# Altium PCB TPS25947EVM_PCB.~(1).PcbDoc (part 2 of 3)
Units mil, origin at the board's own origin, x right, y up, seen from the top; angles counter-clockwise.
Board outline 6500 x 3000 mil, 4 copper layers (L1-Top Layer, L2-GND1, L3-PWR/SIG, L4-Bottom Layer), stack 63.4 mil thick; 232 components, 92 nets, 448 pads, 577 vias.

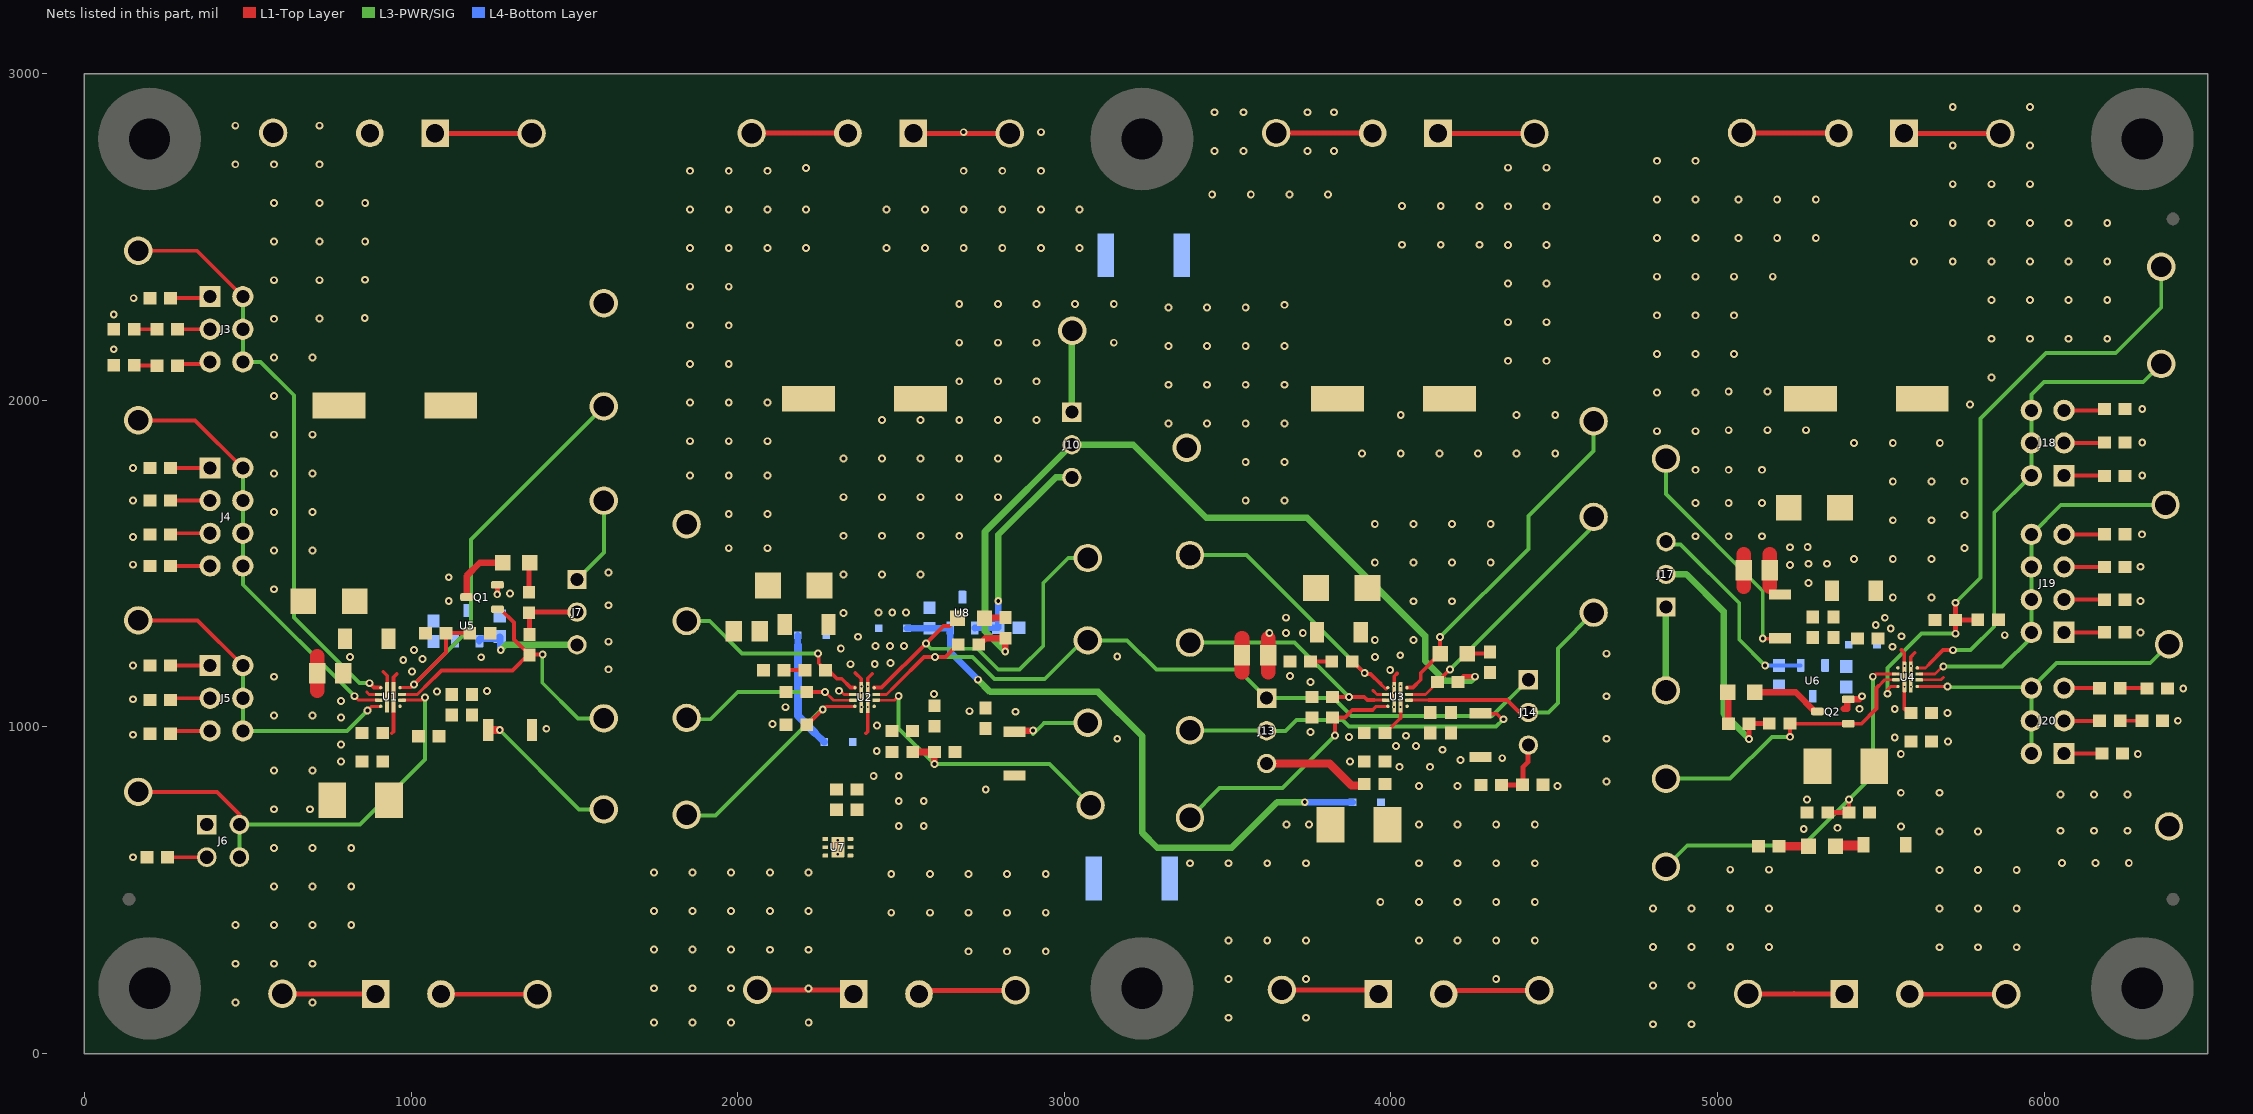
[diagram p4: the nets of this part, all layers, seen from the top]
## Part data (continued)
R38: library part CMP-0023275-5, "RES, 78.7 k, 1%, 0.1 W, 0603", Manufacturer=Yageo, Power_W=100mW, Supplier Part Number 1=311-78.7KHRCT-ND, TempCo="100 ppm/C", Tolerance_%=1%, Value2=0.1W, Value_Code=78k7, ValueDisplayed=78.7k
R39 R40: library part CMP-0016034-2, "RES, 0, 5%, 1 W, 2512", Manufacturer=Samsung, Power_W=1W, Supplier Part Number 1=1276-6000-1-ND, TempCo=ppm/C, Tolerance_%=5%, Value_Code=0000, ValueDisplayed=0
R43 R46: library part CMP-0022735-5, "RES, 100 k, 1%, 0.1 W, 0603", Manufacturer=Yageo, Power_W=100mW, Supplier Part Number 1=311-100KHRCT-ND, TempCo="100 ppm/C", Tolerance_%=1%, Value2=0.1W, Value_Code=100k
S1 S2 S3 S4: library part CMP-0002150-2, "SWITCH TACTILE SPST-NO 0.05A 12V", CurrentRating_mA=50A, Manufacturer="Omron Electronic Components", Supplier Part Number 1=SW1020CT-ND
SH-J3 SH-J4 SH-J5 SH-J6 SH-J7 SH-J10 SH-J11 SH-J12 SH-J13 SH-J16 SH-J19 SH-J20: library part CMP-0003642-1, "Shunt, 100mil, Flash Gold, Black", Manufacturer="Sullins Connector Solutions", Supplier Part Number 1=S9001-ND
TP1 TP6 TP8 TP14 TP15 TP19 TP27 TP28 TP33 TP39 TP44 TP50: library part CMP-0055148-1, "Test Point, Multipurpose, Black, TH", Color=Black, Manufacturer=Keystone, PartNumber=5011, Supplier Part Number 1=36-5011-ND
TP2 TP3 TP4 TP5 TP9 TP11 TP12 TP16 TP17 TP18 TP22 TP23 TP24 TP25 TP29 TP30 TP31 TP32 TP35 TP36 TP37 TP40 TP42 TP43 TP46 TP47 TP48 TP49: library part CMP-0055149-1, "Test Point, Multipurpose, White, TH", Color=White, Manufacturer=Keystone, PartNumber=5012, Supplier Part Number 1=36-5012-ND
TP7 TP13 TP20 TP26 TP34 TP38 TP45 TP51: library part CMP-0055147-1, "Test Point, Multipurpose, Red, TH", Color=Red, Manufacturer=Keystone, PartNumber=5010, Supplier Part Number 1=36-5010-ND
TP10 TP21 TP41: library part CMP-0055150-1, "Test Point, Multipurpose, Orange, TH", Color=Orange, Manufacturer=Keystone, PartNumber=5013, Supplier Part Number 1=36-5013-ND
U1: library part CMP-0090373-1, "2.7- 23V, 5.5 A, 28 mO Reverse Current Blocking eFuse with Input Reverse Polarity Protection", Manufacturer="Texas Instruments", Max Supply Voltage=23V, Min Supply Voltage=2.7V, Nominal Supply Current=450uA, Operating Temperature Range="-40°C to +125°C", Threshold Voltage=1.2/1.1V
U2 U3: library part CMP-0087985-1, "2.7- 23V, 5.5 A, 24.5 mO Reverse Current Blocking eFuse with Input Reverse Polarity Protection", Manufacturer="Texas Instruments", Operating Temperature Range="-40°C to +125°C"
U4: library part CMP-0088329-1, "2.7- 23V, 5.5 A, 28 mO Reverse Current Blocking eFuse with Input Reverse Polarity Protection", Manufacturer="Texas Instruments", Max Supply Voltage=23V, Min Supply Voltage=2.7V, Nominal Supply Current=0.5-6A, Operating Temperature Range="-40°C to +125°C", Output Voltage=42V, Threshold Voltage=1.2/1.1V
U5 U6 U8: library part CMP-0071020-1, "100 mA, Quasi Low-Dropout Linear Voltage Regulator, 3-pin SOT-23, Pb-Free", Manufacturer="Texas Instruments", PackageTopMarking=L0A*XTT, PowerWise=N
U7: library part CMP-0077834-1, "22-V Precision Surge Protection Clamp, DRV0006A (WSON-6)", Alternate Manufacturer="Texas Instruments"
ZZ1: library part CMP-0003616-3
ZZ2: library part CMP-0077236-1
ZZ3: library part CMP-0077237-1
ZZ4: library part CMP-0077238-1

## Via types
v1: diameter 24, hole 12, L1-Top Layer to L4-Bottom Layer, tented both sides, 551 vias
v2: diameter 12, hole 6, L1-Top Layer to L4-Bottom Layer, 24 vias
v3: diameter 19.68, hole 7.87, L1-Top Layer to L4-Bottom Layer, 2 vias

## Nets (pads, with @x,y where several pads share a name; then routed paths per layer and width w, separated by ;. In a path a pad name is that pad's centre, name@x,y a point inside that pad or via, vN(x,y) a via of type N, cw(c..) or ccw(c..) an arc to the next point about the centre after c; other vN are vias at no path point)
AUX_OFF2: J13.1 J14.1 R43.1 TP23.1 U2.3 | length 2350.3
  L1-Top Layer w9: U2.3@2423.77,1099.45 2455.77,1099.45 2483.91,1127.59
  L1-Top Layer w12: 2483.91,1127.59 2570.92,1214.6 v1(2603.81,1214.6) 2636.34,1214.6 2674.2,1252.45 R43.1@2675.18,1252.45
  L3-PWR/SIG w12: v1(2603.81,1214.6) 2718.9,1214.6 2786.32,1147.18 2940.15,1147.18 3057.88,1264.91 TP23.1@3071.9,1264.91 3192.04,1264.91 3281.74,1175.22 3532.26,1175.22 J13.1@3619.32,1088.16 3824.34,1088.16 3879.23,1033.26 4309.47,1033.26 J14.1@4420.6,1144.4
AUX_OFF3: R46.1 TP36.1 U3.3 | length 816.7
  L1-Top Layer w9: U3.3@4055.16,1099.58 4105.98,1099.58 4142.45,1136.05 R46.1@4142.45,1138.04 ; R46.1@4142.4,1138 R46.1@4142.45,1138.04 ; R46.1@4142.45,1147.02 R46.1@4142.45,1138.04 ; v1@4179.97,1175.56 v1(4180.84,1175.56)
  L1-Top Layer w12: R46.1@4142.45,1138.04 v1@4179.97,1175.56
  L3-PWR/SIG w12: v1(4180.84,1175.56) 4620.3,1615.02 TP36.1@4620.3,1642.9
dVdt1: J3.2 J3.4 J3.6 TP2.1 U1.7 | length 1812.3
  L1-Top Layer w12: TP2.1@164.8,2457.9 344.52,2457.9 J3.2@484.95,2317.47 ; v1(872.38,1133.89) 886.02,1120.25 U1.7@907.24,1120.25
  L3-PWR/SIG w12: J3.2@484.95,2317.47 J3.4@484.95,2217.47 J3.6@484.95,2117.47 539.25,2117.47 641.4,2015.32 641.4,1334.9 842.42,1133.89 v1(872.38,1133.89)
dVdt2: R44.2 TP16.1 U2.7 | length 609.5
  L1-Top Layer w12: v1(2245.8,1225) v1@2248.1,1222.7 ; 2248.1,1212.7 2248.1,1195 R44.2@2255.61,1187.49 ; R44.2@2255.61,1186.5 R44.2@2268.31,1173.8 ; R44.2@2268.31,1183.8 2304.64,1147.47 2318.49,1147.47 2345.84,1120.12 U2.7@2358.59,1120.12
  L3-PWR/SIG w12: TP16.1@1843.6,1324.2 1914.4,1324.2 2013.6,1225 v1(2245.8,1225)
dVdt3: R45.2 TP29.1 U3.7 | length 830.5
  L1-Top Layer w9: R45.2@3881.5,1200.4 R45.2@3882.48,1200.4 ; R45.2@3892.7,1200.39 R45.2@3893.68,1200.39 ; 3967.25,1132.42 3982.97,1116.7 3986.65,1116.7 U3.7@3990.2,1120.25
  L1-Top Layer w12: R45.2@3882.48,1200.4 3918.23,1164.65 v1(3919.52,1164.65) 3921.82,1162.35 3937.31,1162.35 3967.25,1132.42
  L3-PWR/SIG w12: TP29.1@3384.6,1526.27 3557.9,1526.27 v1(3919.52,1164.65)
dVdt4: J20.2 J20.4 J20.6 TP49.1 U4.7 | length 1028.5
  L1-Top Layer w9: U4.7@5611,1123.71 v1(5703.18,1123.71)
  L3-PWR/SIG w12: v1(5703.18,1123.71) 5705.48,1121.41 5957.62,1121.41 J20.6@5960.33,1118.7 ; J20.2@5960.33,918.7 J20.4@5960.33,1018.7 J20.6@5960.33,1118.7 ; TP49.1@6381.8,1252.9 6324.3,1195.4 6037.03,1195.4 J20.6@5960.33,1118.7
EN/UVLO1: C6.1 R1.1 R3.2 S1.2 TP12.1 U1.1 | length 454.4
  L1-Top Layer w25: S1.2@1236.56,990.66 1236.62,990.6 v1(1271.6,990.6)
  L3-PWR/SIG w12: v1(1271.6,990.6) 1514.82,747.38 TP12.1@1590.2,747.38
EN/UVLO2: C33.1 R25.1 R28.2 S2.2 TP24.1 U2.1 | length 240.8
  L1-Top Layer w20: S2.2@2844.31,988.12 v1@2903.87,988.12
  L3-PWR/SIG w12: v1@2904.63,978.88 2938.38,1012.63 TP24.1@3071.9,1012.63
  other v1: 2904.63,988.88
EN/UVLO3: C42.1 J13.2 R35.2 S3.2 TP31.1 U3.1 | length 1072.2
  L1-Top Layer w11: S3.2@4273.7,1041.83 4275.21,1040.32 4323.66,1040.32 4340.53,1023.46 v1(4344.04,1023.46)
  L1-Top Layer w12: TP31.1@3384.6,989.93 TP31.1@3385.49,989.04 ; J13.2@3618.43,989.04 J13.2@3619.32,988.16
  L3-PWR/SIG w12: TP31.1@3384.6,989.93 3385.49,989.04 3618.43,989.04 J13.2@3619.32,988.16 3677.49,988.16 3710.75,1021.41 3851.08,1021.41 3871.5,1000.99 4321.58,1000.99 v1(4344.04,1023.46)
EN/UVLO4: C20.1 R13.1 R15.2 S4.2 TP40.1 U4.1 | length 727.4
  L1-Top Layer w11: v1(5138.1,1270.4) 5190.16,1270.4 5190.2,1270.36 S4.2@5191.39,1271.55
  L3-PWR/SIG w12: TP40.1@4841.8,1821.31 4841.8,1713.04 5138.1,1416.74 v1(5138.1,1270.4)
FLTb2: D13.2 TP22.1 U2.4 | length 1126.4
  L1-Top Layer w12: U2.4@2417.86,1120.12 2440.89,1120.12 v1(2576.21,1255.43) 2629.96,1309.18 2649.3,1309.18 D13.2@2672.92,1332.81
  L3-PWR/SIG w12: v1(2576.21,1255.43) 2592.24,1239.4 2733.93,1239.4 2797.77,1175.56 2863.13,1175.56 2935.38,1247.8 2935.38,1440.67 3011.9,1517.2 TP22.1@3071.9,1517.2
FLTb3: D16.2 TP35.1 U3.4 | length 1062.4
  L1-Top Layer w12: U3.4@4049.25,1120.25 4066.89,1120.25 4091.12,1144.47 4091.12,1165.32 D16.2@4150.32,1224.52 v1(4150.32,1274.9)
  L3-PWR/SIG w12: v1(4150.32,1274.9) 4420.6,1545.18 4420.6,1645.28 4620.3,1844.98 TP35.1@4620.3,1935.8
GND1: C1.2 C2.2 C5.2 C6.2 C7.2 C8.2 C9.2 C10.2 C11.2 C12.2 J6.1 NT1.2 R3.1 R4.1 R6.1 R7.1 R8.1 R9.1 R10.1 S1.1 TP8.1 U1.8 | length 39.8
  L1-Top Layer w9: 864.46,1106.64 871.52,1099.58 U1.8@901.34,1099.58
  other v1: 149.31,601.16 785.4,894.17 785.4,945.8 149.31,976.18 1414.08,994.56 785.4,1029.3 785.4,1079.81 149.31,1084.81 1079.74,1108.1 1232.33,1109.56 1604.69,1176.48 149.31,1187.79 1214.81,1213.45 812.93,1214.49 1604.69,1260.97 1604.69,1372.58 1115.57,1385.38 1115.57,1458.18 1604.69,1472.58 149.31,1496.75 149.31,1581.24 149.31,1692.86 149.31,1792.86 89.8,2156.33 89.8,2262.34 150.95,2312.56
GND2: C29.2 C30.2 C32.2 C33.2 C34.2 C35.2 NT3.2 R28.1 R30.1 R31.1 S2.1 TP15.1 U2.8 | length 41.1
  L1-Top Layer w9: v1@2315.75,1108.95 2325.25,1099.45 U2.8@2352.9,1099.45
  other v1: 2759.52,808.83 3162.04,963.85 2106.44,1009.34 2850.6,1046.61 2709.35,1048.25 2146.48,1060.43 2600.86,1100.7 2310.6,1110.6 3162.04,1215.33
GND3: C38.2 C39.2 C41.2 C42.2 C43.2 C44.2 NT4.2 R35.1 R37.1 R38.1 S3.1 TP28.1 U3.8 | length 149.7
  L1-Top Layer w9: 3944.49,1112.37 3957.28,1099.58 U3.8@3984.29,1099.58
  L1-Top Layer w45: 3623.84,1167.01 NT4.2@3623.84,1219.32 3623.84,1271.64
  other v1: 4510.1,819.04 4659.88,833.47 3874.47,894.16 4212.96,899 4340.53,904.38 4158.13,930.04 4659.88,963.75 3871.67,969.62 3754.07,984.3 4659.88,1094.02 3754.07,1138.04 3690.58,1155.5 4659.88,1224.3 3627.52,1287.59 3678.76,1287.59 3730,1287.59 3678.76,1334.43
GND4: C15.2 C16.2 C19.2 C20.2 C21.2 C22.2 C23.2 C24.2 C25.2 C26.2 NT2.2 R15.1 R18.1 R20.1 R21.1 R22.1 R23.1 R36.1 S4.1 TP50.1 U4.8 | length 175.4
  L1-Top Layer w9: U4.8@5616.91,1144.38 5684.02,1144.38 5690.82,1151.18
  L1-Top Layer w45: 5159.9,1429.85 NT2.2@5159.9,1479.2 5159.9,1528.55
  other v1: 6054.4,583.4 6157.05,583.4 6258.8,583.4 6049.92,682.09 6152.57,682.09 6254.32,682.09 5263.72,687.69 5366.72,691.25 5273.92,777.55 6049.92,792.81 6152.57,792.81 6254.32,792.81 6286.35,916.68 5705.24,955.31 6408.78,1018.9 5703.23,1043.01 6425.3,1117.47 5878.98,1280.89 6294.35,1289.24 6294.35,1385.85 5278.62,1440.77 6294.35,1490.5 5221.2,1495.54 5278.18,1499.46 5334.7,1499.46 5755.98,1547.55 5221.2,1550.2 5275.62,1550.85 6299,1589.7 5755.98,1649.3 5755.98,1751.95 6300,1769.3 6300,1871.05 6300,1973.7
ILM1: J4.2 J4.4 J4.6 J4.8 TP3.1 U1.9 | length 1300.2
  L1-Top Layer w9: v1(827.35,1094.08) 839.57,1081.86 U1.9@901.34,1081.86
  L1-Top Layer w12: TP3.1@164.8,1938.7 339.1,1938.7 J4.2@484.95,1792.86
  L3-PWR/SIG w12: J4.2@484.95,1792.86 J4.4@484.95,1692.86 J4.6@484.95,1592.86 J4.8@484.95,1492.86 484.95,1436.45 v1@827.32,1094.08
ILM2: R30.2 TP17.1 U2.9 | length 610.5
  L1-Top Layer w9: R30.2@2219.8,1100.7 R30.2@2219.8,1107.2 ; v1(2267.71,1107.2) 2293.18,1081.73 U2.9@2352.9,1081.73
  L1-Top Layer w12: R30.2@2219.8,1107.2 v1(2267.71,1107.2)
  L3-PWR/SIG w12: TP17.1@1843.6,1027.6 1847.6,1023.6 1916.5,1023.6 2000.1,1107.2 v1(2267.71,1107.2)
ILM3: R37.2 TP30.1 U3.9 | length 723.6
  L1-Top Layer w9: 3948.82,1081.86 U3.9@3984.29,1081.86
  L1-Top Layer w12: R37.2@3820.8,1091.4 v1(3871.67,1091.4) 3918.23,1091.4 3927.77,1081.86 3948.82,1081.86
  L3-PWR/SIG w12: TP30.1@3384.6,1258.1 3704.97,1258.1 v1(3871.67,1091.4)
ILM4: J19.2 J19.4 J19.6 J19.8 TP48.1 U4.9 | length 1153.5
  L1-Top Layer w9: U4.9@5616.91,1162.09 5649.32,1162.09 5665.75,1162.09 5688.39,1184.73 v1(5690.82,1184.73)
  L3-PWR/SIG w12: v1(5690.82,1184.73) 5870.93,1184.73 5960.33,1274.13 J19.2@5960.33,1289.7 J19.4@5960.33,1389.7 J19.6@5960.33,1489.7 J19.8@5960.33,1589.7 6050.43,1679.8 TP48.1@6371.1,1679.8
iTimer1: J5.2 J5.4 J5.6 TP4.1 U1.10 | length 1025.1
  L1-Top Layer w9: v1(866.8,1050.14) 879.82,1063.16 901.34,1063.16
  L1-Top Layer w12: TP4.1@164.8,1326.3 346.44,1326.3 J5.2@484.95,1187.79
  L3-PWR/SIG w12: J5.2@484.95,1187.79 J5.4@484.95,1087.79 J5.6@484.95,987.79 804.45,987.79 v1(866.8,1050.14)
iTimer2: C34.1 TP18.1 U2.10 | length 718.3
  L1-Top Layer w9: C34.1@2219.8,1006.6 C34.1@2219.8,1013.1 ; v1(2260.3,1053.6) 2269.73,1063.03 U2.10@2358.81,1063.03
  L1-Top Layer w12: C34.1@2219.8,1013.1 v1(2260.3,1053.6)
  L3-PWR/SIG w12: TP18.1@1843.6,731 1845.7,728.9 1916.5,728.9 1932.35,728.9 2257.05,1053.6 v1(2260.3,1053.6)
ITimer3: C43.1 TP32.1 U3.10 | length 779.2
  L1-Top Layer w9: 3948.82,1057.25 3954.72,1063.16 U3.10@3990.2,1063.16
  L1-Top Layer w12: v1(3829.1,974.02) 3829.1,1007.86 3829.3,1008.06 3829.3,1029.19 3859.34,1029.19 3881.45,1051.3 3942.86,1051.3 3948.82,1057.25
  L3-PWR/SIG w12: TP32.1@3384.6,721.77 3475.46,812.63 3667.71,812.63 v1(3829.1,974.02)
ITimer4: J18.2 J18.4 J18.6 TP47.1 U4.10 | length 1482.2
  L1-Top Layer w9: U4.10@5611,1180.79 5636.52,1180.79 5649.32,1193.59 5649.32,1194.17
  L1-Top Layer w12: 5649.32,1194.17 5690.16,1235.01 v1(5720.94,1235.01)
  L3-PWR/SIG w12: v1(5720.94,1235.01) 5774.29,1235.01 5846.9,1307.62 5846.9,1655.87 J18.2@5960.33,1769.3 J18.4@5960.33,1869.3 J18.6@5960.33,1969.3 5960.33,2017.38 5999.15,2056.2 6303,2056.2 TP47.1@6358.1,2111.3
NetC7_1: C7.1 J5.1 | length 113
  L1-Top Layer w12: C7.1@271.93,1187.79 J5.1@384.95,1187.79
NetC8_1: C8.1 J5.3 | length 115.1
  L1-Top Layer w12: C8.1@271.93,1082.86 276.86,1087.79 J5.3@384.95,1087.79
NetC9_1: C9.1 J5.5 | length 116.6
  L1-Top Layer w12: C9.1@271.93,979.26 280.46,987.79 J5.5@384.95,987.79
NetC10_1: C10.1 J3.1 | length 123.6
  L1-Top Layer w12: C10.1@263.43,2312.56 380.03,2312.56 J3.1@384.95,2317.47
NetC11_1: C11.1 R12.1 | length 69.3
  L1-Top Layer w12: C11.1@152.8,2217.47 R12.1@222.09,2217.47
NetC12_1: C12.1 R16.1 | length 72.8
  L1-Top Layer w12: C12.1@149.8,2107.1 150.95,2105.95 R16.1@222.09,2105.95
NetC13_1: C13.1 J7.3 U5.1 | length 354.6
  L3-PWR/SIG w20: v1(1274.56,1236.05) 1289.99,1251.48 J7.3@1508.18,1251.48
  L4-Bottom Layer w20: U5.1@1209.3,1262.35 1209.3,1267.61 1211.11,1269.42 1264.53,1269.42 C13.1@1271.6,1276.5 1273.79,1274.31 1273.79,1236.81 v1(1274.56,1236.05) v1@1274.56,1237.69
NetC21_1: C21.1 J18.1 | length 116
  L1-Top Layer w12: J18.1@6060.33,1769.3 6175.03,1769.3 C21.1@6175.93,1768.4
NetC22_1: C22.1 J18.3 | length 116.3
  L1-Top Layer w12: J18.3@6060.33,1869.3 6174.18,1869.3 C22.1@6175.93,1871.05
NetC23_1: C23.1 J18.5 | length 117.4
  L1-Top Layer w12: J18.5@6060.33,1969.3 6171.53,1969.3 C23.1@6175.93,1973.7
NetC24_1: C24.1 J20.1 | length 116
  L1-Top Layer w12: J20.1@6060.33,918.7 C24.1@6176.33,918.7
NetC25_1: C25.1 R41.1 | length 66.6
  L1-Top Layer w12: R41.1@6232.46,1018.87 C25.1@6299,1018.87
NetC26_1: C26.1 R42.1 | length 73.4
  L1-Top Layer w12: R42.1@6232.42,1118.7 6304.83,1118.7 C26.1@6305.53,1118
NetC27_1: C27.1 J17.3 U6.1 | length 634.8
  L3-PWR/SIG w12: J17.3@4841.8,1567.1 4849.86,1559.04 4886.47,1559.04 5066.2,1379.31 5066.2,1267.64 v1(5145.57,1188.27)
  L4-Bottom Layer w12: v1(5145.57,1188.27) C27.1@5188.03,1188.27 5188.38,1188.62 U6.1@5254.13,1188.62
NetC28_1: C28.1 D9.1 U6.2
NetC35_1: C35.1 R44.1 | length 64.5
  L1-Top Layer w9: R44.1@2191.24,1183.87 R44.1@2191.3,1183.8
  L1-Top Layer w12: C35.1@2141.8,1173.87 R44.1@2206.24,1173.87
NetC36_1: C36.1 J10.3 U8.1 | length 647.9
  L3-PWR/SIG w20: v1(2797.8,1385.98) 2797.8,1588.1 2973.5,1763.8 J10.3@3022.9,1763.8
  L4-Bottom Layer w20: U8.1@2725.6,1302.76 2726.32,1303.47 2789.98,1303.47 C36.1@2790.7,1304.19 ; C36.1@2797.8,1303.8 v1(2797.8,1385.98)
NetC37_1: C37.1 D17.1 D18.1 U8.2 | length 1917.4
  L3-PWR/SIG w20: v1(2735.4,1144.6) 2772.8,1107.2 3103.31,1107.2 3238.95,971.55 3238.95,675.66 3284.32,630.3 3511.83,630.3 3651.13,769.6 v1(3735.96,769.6)
  L4-Bottom Layer w20: D17.1@2518.22,1301.8 2518.34,1301.92 2586.76,1301.92 C37.1@2586.88,1302.04 2587.23,1302.4 2650.44,1302.4 U8.2@2650.8,1302.76 2650.8,1229.2 v1(2735.4,1144.6) ; v1(3735.96,769.6) 3882.44,769.6 D18.1@3882.49,769.66
NetC44_1: C44.1 R45.1 | length 64.5
  L1-Top Layer w9: C44.1@3754,1200.47 C44.1@3754.07,1200.4
  L1-Top Layer w12: C44.1@3754.07,1200.4 R45.1@3818.5,1200.4
NetD3_1: D3.1 R11.1 | length 76.7
  L1-Top Layer w15: D3.1@1360.97,1489.15 1361.06,1489.06 R11.1@1361.06,1412.5
NetD3_2: D3.2 Q1.3 | length 191.8
  L1-Top Layer w20: Q1.3@1169.97,1397.68 1169.97,1462.01 1210.56,1502.6 D3.2@1280.66,1502.6
NetD4_2: D4.2 D7.2 | length 81.2
  L1-Top Layer w30: D7.2@5363.1,636.94 D4.2@5444.33,636.94
NetD7_1: D7.1 R17.2 | length 81.9
  L1-Top Layer w25: R17.2@5196.32,634.69 D7.1@5278.18,634.69
NetD8_1: D8.1 R24.1 | length 97.9
  L1-Top Layer w15: D8.1@5029.97,1106.7 D8.1@5030.66,1106
  L1-Top Layer w20: D8.1@5030.66,1106 5031.78,1104.88 5031.78,1011.12 R24.1@5032.9,1010
NetD8_2: D8.2 Q2.3 | length 219
  L1-Top Layer w15: D8.2@5111.6,1104.26 D8.2@5113.34,1106
  L1-Top Layer w20: D8.2@5113.34,1106 5238.88,1106 5297.62,1047.26 Q2.3@5305.5,1047.26
NetD10_2: D10.2 D11.2 | length 361.4
  L4-Bottom Layer w20: 2184.22,1250.2 D11.2@2184.19,1280.7
  L4-Bottom Layer w22: 2236.53,981.82 2264.84,953.51 D10.2@2265.36,954.03
  L4-Bottom Layer w25: 2184.19,1139.05 2184.19,1034.15 2236.53,981.82 ; 2184.22,1139.07 2184.22,1250.2
NetD13_1: D13.1 R26.1 | length 62.6
  L1-Top Layer w20: D13.1@2756.54,1333.75 R26.1@2819.11,1333.75
NetD16_1: D16.1 R34.1 | length 72.2
  L1-Top Layer w9: R34.1@4297.85,1224.52 R34.1@4303.03,1229.7
  L1-Top Layer w12: D16.1@4233,1224.52 R34.1@4297.85,1224.52
NetJ3_3: J3.3 R12.2 | length 99.9
  L1-Top Layer w12: R12.2@285.08,2217.47 J3.3@384.95,2217.47
NetJ3_5: J3.5 R16.2 | length 104.6
  L1-Top Layer w12: R16.2@285.08,2105.95 290.84,2111.71 379.18,2111.71 J3.5@384.95,2117.47
NetJ4_1: J4.1 R7.2 | length 113
  L1-Top Layer w12: R7.2@271.93,1792.86 J4.1@384.95,1792.86
NetJ4_3: J4.3 R8.2 | length 113
  L1-Top Layer w12: R8.2@271.93,1692.86 J4.3@384.95,1692.86
NetJ4_5: J4.5 R9.2 | length 114.5
  L1-Top Layer w12: R9.2@271.93,1589.24 275.54,1592.86 J4.5@384.95,1592.86
NetJ4_7: J4.7 R10.2 | length 113
  L1-Top Layer w12: R10.2@271.93,1492.86 J4.7@384.95,1492.86
NetJ6_3: J6.3 R6.2 | length 112
  L1-Top Layer w12: R6.2@262.67,601.16 J6.3@374.67,601.16
NetJ7_1: J7.1 TP10.1 | length 275.3
  L3-PWR/SIG w12: J7.1@1508.18,1451.48 1590.2,1533.5 TP10.1@1590.2,1692.86
NetJ7_2: J7.2 R5.2 R11.2 | length 214.3
  L1-Top Layer w15: R11.2@1360.97,1351.48 J7.2@1508.18,1351.48 ; R11.2@1361.06,1349.51 1362.32,1348.26 R5.2@1362.32,1282.98
NetJ10_1: J10.1 TP21.1 | length 247.8
  L3-PWR/SIG w20: J10.1@3023.2,1964.1 TP21.1@3023.2,2211.9
NetJ13_3: J13.3 R32.1 | length 327.7
  L1-Top Layer w25: J13.3@3619.32,888.16 3812.38,888.16 3879.52,821.02 R32.1@3919.24,821.02
NetJ14_3: J14.3 R33.1 R38.2 | length 190.5
  L1-Top Layer w15: R33.1@4338.53,822.6 R38.2@4399.94,822.6 ; R38.2@4402.5,822.8 4403.6,823.9 4403.6,876.99 4418.98,892.37 4418.98,942.78 J14.3@4420.6,944.4
NetJ17_1: J17.1 TP41.1 | length 255.5
  L3-PWR/SIG w20: TP41.1@4841.8,1111.62 J17.1@4841.8,1367.1
NetJ17_2: J17.2 R19.2 R24.2 | length 754.3
  L1-Top Layer w15: v1(5095.9,963.56) R24.2@5095.9,1010 5095.95,1010.05 5157.85,1010.05 5158.05,1010.25 R19.2@5158.2,1010.1
  L3-PWR/SIG w20: J17.2@4841.8,1467.1 4904.36,1467.1 5018,1353.45 5018,1041.46 v1(5095.9,963.56)
NetJ19_1: J19.1 R20.2 | length 115.6
  L1-Top Layer w12: J19.1@6060.33,1289.7 R20.2@6175.93,1289.7
NetJ19_3: J19.3 R21.2 | length 115.6
  L1-Top Layer w12: J19.3@6060.33,1389.7 R21.2@6175.93,1389.7
NetJ19_5: J19.5 R22.2 | length 115.6
  L1-Top Layer w12: J19.5@6060.33,1489.7 R22.2@6175.93,1489.7
NetJ19_7: J19.7 R23.2 | length 115.6
  L1-Top Layer w12: J19.7@6060.33,1589.7 R23.2@6175.93,1589.7
NetJ20_3: J20.3 R41.2 | length 109.2
  L1-Top Layer w12: J20.3@6060.33,1018.7 6060.43,1018.8 6169.33,1018.8 R41.2@6169.43,1018.9
NetJ20_5: J20.5 R42.2 | length 109.1
  L1-Top Layer w12: J20.5@6060.33,1118.7 R42.2@6169.43,1118.7
OVCSEL1: J6.2 J6.4 TP5.1 U1.2 | length 1383.7
  L1-Top Layer w9: U1.2@972.5,1082.16 1034.62,1082.16 v1(1042.69,1090.23)
  L1-Top Layer w12: TP5.1@164.8,801.16 405.94,801.16 474.67,732.43 J6.2@474.67,701.16
  L3-PWR/SIG w12: J6.4@474.67,601.16 J6.2@474.67,701.16 843.68,701.16 1042.69,900.16 v1(1042.69,1090.23)
OVLO2: R27.1 R31.2 TP25.1 U2.2 | length 958.5
  L1-Top Layer w9: U2.2@2423.77,1081.73 2480.16,1081.73 v1(2492.95,1094.53)
  L1-Top Layer w20: R27.1@2535.74,923.23 R31.2@2602.3,923.23 v1@2602.3,889.53
  L3-PWR/SIG w12: v1(2492.95,1094.53) 2492.95,995.64 2602.31,886.28 2954.43,886.28 TP25.1@3080.36,760.35
  other v1: 2602.34,886.28
OVLO3: J14.2 TP37.1 U3.2 | length 813.9
  L1-Top Layer w9: U3.2@4055.16,1081.86 4115.1,1081.86 4115.8,1082.56 ; J14.2@4420.6,1044.4 J14.2@4426.2,1050
  L1-Top Layer w12: 4115.8,1082.56 4355.32,1082.56 4393.48,1044.4 J14.2@4420.6,1044.4
  L3-PWR/SIG w12: J14.2@4420.6,1044.4 4482.33,1044.4 4510.78,1072.85 4510.78,1240.48 TP37.1@4620.3,1350
OVLO4: R14.1 R18.2 TP43.1 U4.2 | length 1251
  L1-Top Layer w9: v1(5475,1153.89) 5483.2,1162.09 U4.2@5546.04,1162.09
  L1-Top Layer w12: v1(5401.66,777.55) 5401.66,738.39 R14.1@5402.02,738.02
  L1-Top Layer w15: TP43.1@4852.64,551.91 TP43.1@4852.64,571.91 ; R18.2@5336.91,738.02 R14.1@5402.02,738.02
  L3-PWR/SIG w12: TP43.1@4841.8,571.91 4906.89,637 5261.11,637 v1(5401.66,777.55) 5475,850.89 v1(5475,1153.89)
PG1: Q1.1 R5.1 TP11.1 U1.3 | length 989.3
  L1-Top Layer w9: U1.3@972.21,1099.58 1019.08,1099.58 1042.47,1122.97 1042.69,1122.97
  L1-Top Layer w12: 1042.69,1122.97 1092.83,1173.11 1092.83,1173.33 1310.49,1173.33 1359.73,1222.57 R5.1@1362.32,1219.98 ; Q1.1@1264.46,1360.28 1273.92,1360.28 1314.99,1319.21 1314.99,1268.3 1362.32,1220.97 R5.1@1362.32,1219.98 ; v1(1402.99,1221.26) 1363.59,1221.26 R5.1@1362.32,1219.98
  L3-PWR/SIG w12: v1@1401.8,1221.26 1401.8,1135.4 1510.99,1026.21 TP11.1@1590.2,1026.21
PG4: Q2.1 R19.1 TP42.1 U4.3 | length 890.4
  L1-Top Layer w9: 5493.02,1125.68 5511.72,1144.38 U4.3@5546.04,1144.38
  L1-Top Layer w12: R19.1@5221.2,1010.1 R19.1@5221.44,1009.86 ; v1(5221.44,969.73) R19.1@5221.44,1009.86 ; 5493.02,1125.68 5486.77,1119.42 5486.77,1056.43 5440.2,1009.86 Q2.1@5399.99,1009.86 R19.1@5221.44,1009.86
  L3-PWR/SIG w12: TP42.1@4841.8,841.6 5037.9,841.6 5166.03,969.73 v1(5221.44,969.73)
PGND: C31.2 C36.2 C37.2 C40.2 D12.2 D14.2 D15.2 J8.2 J9.1 J11.2 J12.1 NT3.1 NT4.1 TP14.1 TP19.1 TP27.1 TP33.1 U7.1 U7.2 U7.3 U7.7@2306.7,631.6 U8.3 | length 1303.2
  L1-Top Layer w11: D15.2@3762.79,1433.17 D15.2@3770.75,1425.21
  L1-Top Layer w15: TP14.1@2027.1,2825.5 TP14.1@2027.85,2824.75 ; TP14.1@2042.42,2817.87 2337.12,2817.87 J8.2@2337.87,2817.12 ; TP19.1@2059.33,195.52 2060.08,194.77 2354.78,194.77 J9.1@2355.53,194.03 ; TP27.1@3648.02,2818.62 3648.77,2817.87 3943.47,2817.87 J11.2@3944.22,2817.12 ; TP33.1@3665.67,195.52 3666.42,194.77 3961.12,194.77 J12.1@3961.87,194.03
  L1-Top Layer w45: 3543.84,1167.01 NT4.1@3543.84,1219.32 3543.84,1271.64
  other v1: 2217.35,95.01 1743.45,95.41 1861.7,95.41 1979.95,95.41 3502.85,109.64 3739.36,109.64 1743.4,200.04 1861.65,200.04 1979.9,200.04 2217.3,199.64 3502.85,227.89 3739.36,227.89 1743.4,318.3 1861.65,318.3 1979.9,318.3 2099.05,317.9 2217.3,317.9 3502.85,346.14 3621.1,346.14 3739.36,346.14 2099.05,436.15 2217.3,436.15 1743.4,436.55 1861.65,436.55 1979.9,436.55 2099.05,554.4 2217.3,554.4 1743.4,554.8 1861.65,554.8 1979.9,554.8 3384.6,582.65 3502.85,582.65 3621.1,582.65 3739.36,582.65 3680.02,701.72 3749.1,701.72 1972.65,1547.21 2090.9,1547.21 1972.6,1651.85 2090.85,1651.85 3555.24,1692.84 3673.49,1692.84 1854.35,1770.1 1972.6,1770.1 2090.85,1770.1 3555.24,1811.09 3673.49,1811.09 1854.3,1874.74 1972.55,1874.74 2090.8,1874.74 3318.74,1929.34 3436.99,1929.34 3555.24,1929.34 3673.49,1929.34 1854.3,1992.99 1972.55,1992.99 2090.8,1992.99 3318.74,2047.6 3436.99,2047.6 3555.24,2047.6 3673.49,2047.6 1854.3,2111.24 1972.55,2111.24 3318.74,2165.85 3436.99,2165.85 3555.24,2165.85 3673.49,2165.85 1854.3,2229.49 1972.55,2229.49 3318.74,2284.1 3436.99,2284.1 3555.24,2284.1 3673.75,2292.3 1854.3,2347.74 1972.55,2347.74 1854.3,2466 1972.55,2466 2090.8,2466 2209.06,2466 1854.3,2584.25 1972.55,2584.25 2090.8,2584.25 2209.06,2584.25 3452.64,2630.25 3570.9,2630.25 3689.15,2630.25 3807.4,2630.25 1854.3,2702.5 1972.55,2702.5 2090.8,2702.5 2209.31,2710.7 3459.98,2763.5 3548.49,2763.5 3744.83,2763.5 3825.4,2763.5 3459.98,2881.75 3548.49,2881.75 3744.83,2881.75 3825.4,2881.75
  other v3: 2306.7,609.95 2306.7,653.25
PGND1: C3.2 C13.2 C14.2 D1.2 D2.2 J1.1 J2.2 NT1.1 Q1.2 TP1.1 TP6.1 U5.3 | length 435.9
  L1-Top Layer w9: v1@719.99,2485.19 v1@721.39,2483.79 ; v1@719.99,2603.44 v1@721.39,2602.04
  L1-Top Layer w15: TP1.1@577.8,2819 TP1.1@578.55,2818.25 ; TP6.1@595.83,183.62 596.2,183.25 597.33,182.12 J1.1@892.03,182.12 ; J2.2@873.25,2818.25 J2.2@874,2817.5 ; v1@1264.14,1406.39 Q1.2@1264.14,1434.76
  L1-Top Layer w45: 712.8,1111.49 NT1.1@712.8,1163.8 712.8,1216.11
  other v1: 462.19,156.7 698.69,156.7 462.19,274.95 580.44,274.95 698.69,274.95 462.19,393.2 580.44,393.2 698.69,393.2 816.94,393.2 580.44,511.46 698.69,511.46 816.94,511.46 580.44,629.71 698.69,629.71 816.94,629.71 580.44,747.96 691.05,748 580.44,866.21 698.69,866.21 580.44,1035.37 698.69,1035.37 580.44,1153.62 1263.82,1406.07 1303.14,1408.81 580.27,1421.62 580.27,1539.88 698.52,1539.88 580.27,1658.13 698.52,1658.13 580.27,1776.38 698.52,1776.38 580.27,1894.63 698.52,1894.63 580.27,2012.88 580.27,2131.13 698.52,2131.13 580.27,2249.39 719.29,2250.79 858.3,2252.19 580.27,2367.64 719.99,2367.64 859,2369.04 580.27,2485.89 719.99,2485.89 859.7,2485.89 580.27,2604.14 719.99,2604.14 859.7,2604.14 462.02,2722.39 580.27,2722.39 719.99,2722.39 462.02,2840.64 719.99,2840.64
PGND4: C17.2 C27.2 C28.2 D5.1 D6.2 J15.2 J16.1 NT2.1 Q2.2 R17.1 TP39.1 TP44.1 U6.3 | length 781.6
  L1-Top Layer w15: TP39.1@5074.52,2818.62 5075.27,2817.87 5369.97,2817.87 J15.2@5370.72,2817.12 ; TP44.1@5092.92,182.87 5387.62,182.87 J16.1@5388.37,182.12 ; 5233.67,184 5234.42,183.25
  L1-Top Layer w20: 5385.4,1055.5 5397.1,1055.5 5397.47,1055.87 5397.47,1082.85 Q2.2@5399.08,1084.46 ; v1(5441.9,1093.9) 5433.31,1085.31 5400.63,1085.31 Q2.2@5399.99,1084.66 ; Q2.2@5399.08,1084.46 5399.79,1084.46 Q2.2@5399.99,1084.66 ; Q2.2@5399.08,1084.46 5399.28,1084.66 Q2.2@5399.99,1084.66
  L1-Top Layer w45: 5079.9,1429.85 NT2.1@5079.9,1479.2 5079.9,1528.55
  other v1: 4802.22,89.92 4920.47,89.92 4802.22,208.18 4920.47,208.18 4802.22,326.43 4920.47,326.43 5038.72,326.43 5156.97,326.43 4802.22,444.68 4920.47,444.68 5038.72,444.68 5156.97,444.68 5038.72,562.93 5156.97,562.93 5434.8,1055.5 4932.22,1583.84 5033.87,1583.84 5135.52,1583.84 4932.22,1685.48 5033.87,1685.48 5135.52,1685.48 4932.22,1787.13 5033.87,1787.13 5135.52,1787.13 4813.97,1905.38 4932.22,1905.38 5033.87,1908.47 5152.12,1908.47 5270.37,1908.47 4813.97,2023.63 4932.22,2023.63 5033.87,2026.72 5152.12,2026.72 4813.97,2141.89 4932.22,2141.89 5050.47,2141.89 4813.97,2260.14 4932.22,2260.14 5050.47,2260.14 4813.97,2378.39 4932.22,2378.39 5050.47,2378.39 5168.73,2378.39 4813.97,2496.64 4932.22,2496.64 5064,2496.64 5182.25,2496.64 5300.51,2496.64 4813.97,2614.89 4932.22,2614.89 5064,2614.89 5182.25,2614.89 5300.51,2614.89 4813.97,2733.14 4932.22,2733.14
PGTH1: R2.1 R4.2 TP9.1 U1.4 | length 1414
  L1-Top Layer w9: U1.4@966.3,1120.25 999.43,1120.25 v1(1009.27,1130.09) ; R4.2@1177.97,1288.82 R4.2@1179.68,1287.11 R4.2@1181.42,1285.37
  L1-Top Layer w12: v1(1009.27,1130.09) 1107.04,1227.86 R2.1@1107.04,1287.12 R4.2@1179.68,1287.11
  L3-PWR/SIG w12: v1(1009.27,1130.09) 1183.2,1304.01 1183.2,1574.35 TP9.1@1590.2,1981.35
PGTH4: R29.1 R36.2 TP46.1 U4.4 | length 1957.2
  L1-Top Layer w9: v1(5519.99,1101.72) 5519.99,1113.87 5529.83,1123.71 U4.4@5551.95,1123.71
  L1-Top Layer w15: v1(5728.3,1285.5) R29.1@5728.3,1327.4 v1(5728.3,1380.08) ; R29.1@5728.8,1327.9 R29.1@5731.5,1327.9 ; R29.1@5732,1327.4 R29.1@5731.5,1327.9 ; R36.2@5795.8,1327.9 R29.1@5731.5,1327.9 ; R36.2@5799.5,1327.9 R36.2@5800,1328.4
  L3-PWR/SIG w12: v1(5519.99,1101.72) 5519.99,1181 5624.48,1285.5 v1(5728.3,1285.5) ; v1(5728.3,1380.08) 5805.02,1456.8 5805.02,1944.82 6004.59,2144.4 6218.64,2144.4 6358.1,2283.86 TP46.1@6358.1,2408.91
VCC: J10.2 R26.2 R34.2 R43.2 R46.2 | length 2539.6
  L1-Top Layer w15: R46.2@4205.4,1138 4221.24,1153.85 v1(4257.16,1153.85)
  L1-Top Layer w20: R43.2@2738.17,1252.45 2739.16,1252.45 2758.41,1271.71 R26.2@2820.06,1271.71 ; v1@2819.58,1231.75 R26.2@2819.58,1271.24
  L3-PWR/SIG w20: v1(2819.11,1231.27) 2757.1,1293.28 2757.1,1598 J10.2@3022.9,1863.8 3210.79,1863.8 3434.44,1640.15 3742.85,1640.15 4104.4,1278.6 4104.4,1202.4 4165.85,1140.95 4244.26,1140.95 v1(4257.16,1153.85)
VIN1: C1.1 C2.1 C14.1 D1.1 J1.2 R1.2 TP13.1 U1.5 U5.2 | length 496
  L1-Top Layer w11: C2.1@921.86,983.17 C2.1@921.86,989.67 ; 941.3,980.48 946.42,985.6 946.42,1090.72 946.42,1090.91 946.42,1103.56 946.42,1152.24 956.12,1161.94
  L1-Top Layer w11.8: C2.1@921.61,980.48 C2.1@926.73,985.6
  L1-Top Layer w15: J1.2@1092.4,181.75 TP13.1@1387.1,181.75
  other v1: 1003.16,1169.98 976.14,1204.82 1034.62,1207.69 1009.27,1235.76
VIN2: C29.1 C30.1 D10.1 D17.2 J9.2 R25.2 R27.2 R39.1 TP26.1 U2.5 U7.4 U7.5 U7.6 | length 485
  L1-Top Layer w11: 2392.86,980.35 2397.98,985.47 2397.98,1090.59 2397.98,1090.78 2397.99,1149.27 2411.58,1162.86
  L1-Top Layer w15: J9.2@2555.9,193.65 TP26.1@2850.6,193.65
  other v1: 2706.68,313.1 2824.93,313.1 2943.18,313.1 2470.17,431.35 2588.42,431.35 2706.68,431.35 2824.93,431.35 2943.18,431.35 2470.17,549.6 2588.42,549.6 2706.68,549.6 2824.93,549.6 2943.18,549.6 2493.04,696.86 2569.67,696.86 2493.04,773.49 2569.67,773.49 2416.4,850.13 2493.04,850.13 2425.8,926.8 2426.64,1004.42 2419.53,1192.28 2467.4,1195.95 2422.34,1247.63 2465.93,1247.63 2509.52,1247.63 2431.51,1350.37 2473.17,1350.37 2514.82,1350.37
  other v2: 2398.23,1060.43 2398.23,1082.43 2398.23,1103.43 2398.23,1124.43
VIN3: C38.1 C39.1 D14.1 D18.2 J12.2 R32.2 R33.2 R39.2 TP38.1 U3.5 | length 420.8
  L1-Top Layer w11: C38.1@3989.81,981.66 3989.81,988.16 4028.63,1026.97 4029.57,1026.97 U3.5@4029.57,1090.72
  L1-Top Layer w15: J12.2@4162.25,193.65 TP38.1@4456.95,193.65
  other v1: 4322,227.89 4085.5,346.14 4203.75,346.14 4322,346.14 4440.26,346.14 3967.25,464.39 4085.5,464.39 4203.75,464.39 4322,464.39 4440.26,464.39 4085.5,582.65 4203.75,582.65 4322,582.65 4440.26,582.65 4085.5,700.9 4203.75,700.9 4322,700.9 4440.26,700.9 4085.5,819.15 4203.75,819.15 4025.61,877.95 4119.18,877.95 4015.71,941.45 4076.12,941.45 4045.6,973
  other v2: 4029.63,1060.56 4029.63,1082.56 4029.63,1103.56 4029.62,1124.56
VIN4: C15.1 C16.1 D4.1 D5.2 D9.2 J16.2 R13.2 R14.2 TP51.1 U4.5 | length 495.5
  L1-Top Layer w11: 5562.85,1235.43 5571.63,1226.65 U4.5@5571.63,1153.24 5571.63,1054.38 C16.1@5583,1043.01
  L1-Top Layer w15: J16.2@5588.75,181.75 TP51.1@5883.45,181.75
  other v1: 5678.96,325.43 5797.21,325.43 5915.46,325.43 5678.96,443.68 5797.21,443.68 5915.46,443.68 5678.96,561.93 5797.21,561.93 5915.46,561.93 5678.96,680.18 5797.21,680.18 5561.4,694.73 5560.71,798.43 5678.96,798.43 5560.71,916.68 5542.1,967.6 5542.3,1054.7 5535.81,1245.47 5562.85,1277.7 5529.83,1301.7 5484.03,1312.13 5511.72,1334.18
  other v2: 5571.57,1123.07 5571.57,1145.07 5571.57,1166.07 5571.57,1187.07
VOUT1: C3.1 C5.1 D2.1 J2.1 R2.2 TP7.1 U1.6 | length 377.9
  L1-Top Layer w11: 914.57,1168.81 926.93,1156.45 U1.6@926.93,1090.72
  L1-Top Layer w15: J2.1@1074.38,2817.13 TP7.1@1369.08,2817.13
VOUT2: C31.1 C32.1 D11.1 D12.1 J8.1 R40.1 TP20.1 U2.6 | length 376.8
  L1-Top Layer w11: 2360.18,1165.1 2378.09,1147.2 2378.09,1090.99 U2.6@2378.49,1090.59
  L1-Top Layer w15: J8.1@2538.25,2816.75 TP20.1@2832.95,2816.75
  other v1: 2345.09,1192.14 2315.75,1239.9 2368.65,1276.13 2323.64,1348.55 2323.64,1466.8 2441.89,1466.8 2560.15,1466.8 2323.64,1585.06 2441.89,1585.06 2560.15,1585.06 2678.4,1585.06 2323.64,1703.31 2441.89,1703.31 2560.15,1703.31 2678.4,1703.31 2796.65,1703.31 2323.64,1821.56 2441.89,1821.56 2560.15,1821.56 2678.4,1821.56 2796.65,1821.56 2441.89,1939.81 2560.15,1939.81 2678.4,1939.81 2796.65,1939.81 2914.9,1939.81 2678.4,2058.06 2796.65,2058.06 2914.9,2058.06 2678.4,2176.31 2796.65,2176.31 2914.9,2176.31 3151.4,2176.31 2678.4,2294.57 2796.65,2294.57 2914.9,2294.57 3033.15,2294.57 3151.4,2294.57 2455.35,2466 2573.6,2466 2691.86,2466 2810.11,2466 2928.36,2466 3046.61,2466 2455.35,2584.25 2573.6,2584.25 2691.86,2584.25 2810.11,2584.25 2928.36,2584.25 3046.61,2584.25 2691.86,2702.5 2810.11,2702.5 2928.36,2702.5 2691.86,2820.76 2928.36,2820.76
  other v2: 2378.43,1060.43 2378.43,1082.43 2378.43,1103.43 2378.43,1124.43
VOUT3: C40.1 C41.1 D15.1 J11.1 R40.2 TP34.1 U3.6 | length 371
  L1-Top Layer w11: U3.6@4009.88,1090.72 4009.88,1154.95 4018.44,1163.51
  L1-Top Layer w15: J11.1@4144.6,2816.75 TP34.1@4439.3,2816.75
  other v1: 3997.52,1173.93 3951.5,1214.6 4028.35,1219.4 3950.45,1266.56 4068.7,1266.56 4068.7,1384.81 4186.96,1384.81 3950.45,1503.06 4068.7,1503.06 4186.96,1503.06 4305.21,1503.06 3950.45,1621.31 4068.7,1621.31 4186.96,1621.31 4305.21,1621.31 3911.72,1837.08 4029.97,1837.08 4148.22,1837.08 4266.47,1837.08 4384.72,1837.08 4502.97,1837.08 4029.97,1955.33 4384.72,1955.33 4502.97,1955.33 4358,2120.8 4476.25,2120.8 4358,2239.05 4476.25,2239.05 4358,2357.3 4476.25,2357.3 4034.17,2476.05 4152.42,2476.05 4270.68,2476.05 4358,2475.56 4476.25,2475.56 4034.17,2594.3 4152.42,2594.3 4270.68,2594.3 4358,2593.81 4476.25,2593.81 4358,2712.06 4476.25,2712.06
  other v2: 4009.83,1060.56 4009.83,1082.56 4009.83,1103.56 4009.83,1124.56
VOUT4: C17.1 C19.1 D6.1 J15.1 R29.2 TP45.1 U4.6 | length 373.2
  L1-Top Layer w11: U4.6@5591.32,1153.24 5591.72,1153.64 5591.72,1214.69 5603.68,1226.65
  L1-Top Layer w15: J15.1@5571.1,2816.75 TP45.1@5865.8,2816.75
  other v1: 5536.2,1396.29 5654.45,1396.29 5417.95,1514.55 5536.2,1514.55 5654.45,1514.55 5536.2,1632.8 5654.45,1632.8 5536.2,1751.05 5654.45,1751.05 5417.95,1869.3 5536.2,1869.3 5680.2,1869.4 5772.7,1987.55 5838,2070.25 5838,2188.5 5956.26,2188.5 6074.51,2188.5 6192.76,2188.5 5838,2306.75 5956.26,2306.75 6074.51,2306.75 6192.76,2306.75 5601.5,2425 5719.75,2425 5838,2425 5956.26,2425 6074.51,2425 6192.76,2425 5601.5,2543.26 5719.75,2543.26 5838,2543.26 5956.26,2543.26 6074.51,2543.26 6192.76,2543.26 5719.75,2661.51 5838,2661.51 5956.26,2661.51 5719.75,2779.76 5956.26,2779.76 5719.75,2898.01 5956.26,2898.01
  other v2: 5591.37,1123.07 5591.37,1145.07 5591.37,1166.07 5591.37,1187.07
pads on no net: FID1.1 FID2.1 FID3.1 FID4.1 FID5.1 FID6.1 H1.1 H2.1 H3.1 H4.1 H5.0 H6.0 H7.0 H8.0 H11.1 H12.1 H13.0 H14.0 SH-J3.0 SH-J4.0 SH-J5.0 SH-J6.0 SH-J7.0 SH-J10.0 SH-J11.0 SH-J12.0 SH-J13.0 SH-J16.0 SH-J19.0 SH-J20.0 U7.7@2306.7,613.88 U7.7@2306.7,649.32

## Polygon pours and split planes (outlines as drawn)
GND1 on L1-Top Layer "L1-TOP_LAYER_GND1_P118" (solid, remove dead copper, pour order 118): 1656.11,40.4 1671.4,55.69 1671.4,2896.7 1578.1,2990 82.9,2990 26.8,2933.9 26.8,59.6 46,40.4
VOUT1 on L1-Top Layer "L1-TOP_LAYER_VOUT1_P108" (solid, remove dead copper, pour order 108): 1068,1475.92 1164.88,1572.8 1653.8,1572.8 1671.4,1590.4 1671.4,2923 1633.7,2960.7 1632.2,2959.2 1514.55,2959.2 995.8,2959.2 970.7,2934.1 970.7,1984.01 769.39,1782.7 769.39,1325.11 773.68,1320.82 823.35,1320.82 846.15,1298.02 846.15,1171.15 862.7,1154.6 929.8,1154.6 929.8,1194.31 997.81,1262.32 1057.32,1262.32 1068,1273
GND2 on L1-Top Layer "L1-TOP_LAYER_GND2_P158" (solid, remove dead copper, pour order 158): 1691.45,2906.45 1692.66,54.52 1715.09,32.1 3159.3,32.1 3232.6,105.4 3232.6,2901.7 3173.6,2960.7 1745.7,2960.7
PGND on L1-Top Layer "L1-TOP_LAYER_PGND_P132" (solid, remove dead copper, pour order 132): 2327.2,691 2319.3,698.9 2178.35,698.9 2021.55,850.74 2021.55,1349.48 2036.83,1364.76 2170.16,1364.76 2184.96,1379.56 2184.96,1764.17 2407.5,1986.71 2407.5,2920.9 2368.74,2959.66 1727.69,2959.65 1692.04,2924.01 1692.04,55.14 1706.84,40.34 2421.04,40.34 2436.39,55.69 2436.39,301.7 2327.2,410.89
VOUT2 on L1-Top Layer "L1-TOP_LAYER_VOUT2_P142" (solid, remove dead copper, pour order 142): 3232.6,2354.29 3232.6,1408.67 3218.38,1394.45 2435.97,1394.45 2382.45,1340.92 2382.45,1137.83 2368.5,1137.83 2203.91,1302.43 2203.91,1756.12 2416.8,1969.01 2416.8,2912.85 2459.75,2955.8 3034.32,2955.8 3067.56,2923.42 3067.56,2771.06 3232.6,2606.01
VIN2 on L1-Top Layer "L1-TOP_LAYER_VIN2_P138" (solid, remove dead copper, pour order 138): 2462.26,62.25 2483.91,40.6 3035.13,40.6 3067.3,72.77 3067.3,288.81 3232.6,454.11 3232.6,763.28 3210.8,785.08 2604.25,785.08 2492.95,896.37 2492.95,1006.65 2480.37,1019.23 2422.37,1019.23 2398.06,1043.54 2394.4,1043.54 2370.09,1019.23 2350.28,1019.23 2338.82,1007.78 2338.82,622.53 2338.82,419.73 2462.26,296.29
GND4 on L1-Top Layer "L1-TOP_LAYER_GND4_P218" (solid, remove dead copper, pour order 218): 4713.4,80.2 4753,40.6 6179,40.6 6464.2,325.8 6464.2,2669.21 6175.93,2957.48 4840.08,2957.48 4713.4,2830.8
GND3 on L1-Top Layer "L1-TOP_LAYER_GND3_P174" (solid, remove dead copper, pour order 174): 3249.1,97.09 3305.58,40.6 4671.4,40.6 4695.4,64.6 4695.4,2885.6 4636,2945 3290.46,2945 3249,2903.54
VIN1 on L1-Top Layer "L1-TOP_LAYER_VIN1_P110" (solid, remove dead copper, pour order 110): 941,1190.22 1002.26,1251.48 1028.53,1251.48 1049.9,1230.11 1049.9,1193.17 1006.13,1149.4 941,1149.4
VIN1 on L1-Top Layer "L1-TOP_LAYER_VIN1_P102" (solid, remove dead copper, pour order 102): 1646.09,911.84 1671.4,886.53 1671.4,55.69 1655.41,39.7 1503.2,39.7 1015.24,39.7 999.2,55.74 999.2,271.8 887.26,383.74 887.26,637.19 887.26,1007.91 898.72,1019.36 928.76,1019.36 941,1031.6 951.8,1031.6 979.18,1004.22 1025.39,1004.22 1041.39,988.22 1041.39,940.22 1069.77,911.84
PGND4 on L1-Top Layer "L1-TOP_LAYER_PGND4_P198" (solid, remove dead copper, pour order 198): 5241.83,585.7 5217.29,610.24 5217.29,780.84 5242.85,806.4 5401.8,806.4 5413.77,818.37 5413.77,951.12 5406.54,958.35 5079.85,958.35 5054.9,983.3 5054.9,1309.99 5115.6,1370.69 5115.6,1539.62 5175.32,1599.34 5274.23,1599.34 5292,1617.11 5292,1716.02 5292,1848.56 5456.1,2012.66 5456.1,2872.6 5456.1,2921.2 5419.82,2957.48 4753.68,2957.48 4713.77,2917.57 4713.78,65.62 4739.17,40.23 5440.2,40.23 5477.17,75.84 5477.17,229.99 5477.17,448.39 5477.17,558.13 5449.6,585.7
PGND on L1-Top Layer "L1-TOP_LAYER_PGND_P136" (solid, remove dead copper, pour order 136): 4033.53,262.43 4033.53,277.8 3922.85,388.48 3922.85,727.56 3815.8,834.61 3586.66,834.61 3569.32,851.95 3569.32,1302.32 3636.74,1369.74 3865.56,1369.74 3870.51,1374.69 3870.51,1603.51 3870.51,1853.94 4005.5,1988.93 4005.5,2927.18 3987.68,2945 3290.46,2945 3249.09,2903.63 3249.09,97.1 3306.48,39.7 4004.66,39.7 4033.53,68.56 4033.53,195.15
VIN3 on L1-Top Layer "L1-TOP_LAYER_VIN3_P160" (solid, remove dead copper, pour order 160): 4307.03,797.97 4320.01,784.99 4683.34,784.99 4695.4,772.93 4695.4,287.52 4695.4,64.6 4671.03,40.23 4085.26,40.23 4066.97,58.52 4052.34,73.15 4052.34,282.71 3949.81,385.24 3949.81,804.96 3949.81,1010.2 3961.27,1021.66 4001.85,1021.66 4029.57,1049.38 4076.12,1002.83 4076.12,966.08 4179.54,862.66 4280.71,862.66 4307.03,836.34
VOUT3 on L1-Top Layer "L1-TOP_LAYER_VOUT3_P168" (solid, remove dead copper, pour order 168): 4114,1282.7 4678.65,1282.7 4695.4,1299.46 4695.4,2234.3 4695.4,2915.3 4665.7,2945 4035.36,2945 4020.79,2930.44 4020.79,2736.18 4020.79,1976.24 3885.8,1841.25 3885.8,1258.09 4011.83,1132.06 4108.98,1229.21 4108.98,1277.68
PGND1 on L1-Top Layer "L1-TOP_LAYER_PGND1_P100" (solid, remove dead copper, pour order 100): 978.2,53.6 964.3,39.7 408.7,39.7 380.95,67.45 380.95,470.16 432.76,521.98 520.38,521.98 557.2,558.79 557.2,2416 394.18,2579.02 394.18,2931.41 420.25,2957.48 932.92,2957.48 959.37,2931.03 959.37,1994.84 754.1,1789.57 754.1,870.87 790.61,834.36 855.08,834.36 872.38,817.06 872.38,376.57 978.2,270.74
PGND1 on L1-Top Layer "L1-TOP_LAYER_PGND1_P098" (solid, remove dead copper, pour order 98): 1231.53,1454.75 1225.62,1448.85 1225.62,1393.24 1229.74,1388.22 1315.32,1388.22 1325.75,1398.65 1325.75,1444.66 1315.66,1454.75
VOUT4 on L1-Top Layer "L1-TOP_LAYER_VOUT4_P206" (solid, remove dead copper, pour order 206): 5930.76,2039.26 6452.66,2039.26 6457.48,2044.08 6457.48,2891.89 6391.58,2957.79 6390.29,2956.5 5973.23,2956.5 5503.3,2956.5 5469.69,2922.89 5469.56,1998.48 5311.32,1840.24 5311.32,1588.78 5425.7,1474.4 5425.7,1404.06 5462.67,1367.1 5528.38,1367.1 5585.41,1310.07 5585.41,1193.04 5591.37,1187.07 5597.22,1192.92 5597.22,1198.53 5598.04,1198.53 5614.75,1215.24 5628.65,1215.24 5683.2,1269.8 5683.2,1791.7
VIN4 on L1-Top Layer "L1-TOP_LAYER_VIN4_P200" (solid, remove dead copper, pour order 200): 5495.1,669.31 5430.33,734.08 5430.33,969.73 5566.59,1105.99 5577.11,1105.99 5616.6,1066.5 5616.6,914.4 5843.31,687.69 6084.3,446.7 6084.3,77.38 6046.71,39.78 5535.52,39.78 5495.1,80.2
VIN4 on L1-Top Layer "L1-TOP_LAYER_VIN4_P204" (solid, remove dead copper, pour order 204): 5545.33,1226.29 5494.71,1226.29 5471.21,1249.79 5471.21,1337.1 5481.51,1347.4 5524.5,1347.4 5578.3,1293.6 5578.3,1200.5 5576.33,1198.53 5565.72,1198.53 5565.72,1205.9
EN/UVLO4 on L1-Top Layer "L1-Top Layer-EN/UVLO4" (solid, remove dead copper, pour order 202): 5498,1205.9 5551.06,1205.9 5556.64,1200.33 5556.64,1180.17 5551.94,1175.48 5457.69,1175.48 5457.1,1174.89 5396.56,1235.43 5130.88,1235.43 5123.68,1242.63 5123.68,1282.62 5134.03,1292.97 5444.53,1292.97 5452,1285.5 5452,1251.9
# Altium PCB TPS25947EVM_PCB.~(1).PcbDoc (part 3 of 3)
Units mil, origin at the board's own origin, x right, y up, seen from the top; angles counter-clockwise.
Board outline 6500 x 3000 mil, 4 copper layers (L1-Top Layer, L2-GND1, L3-PWR/SIG, L4-Bottom Layer), stack 63.4 mil thick; 232 components, 92 nets, 448 pads, 577 vias.

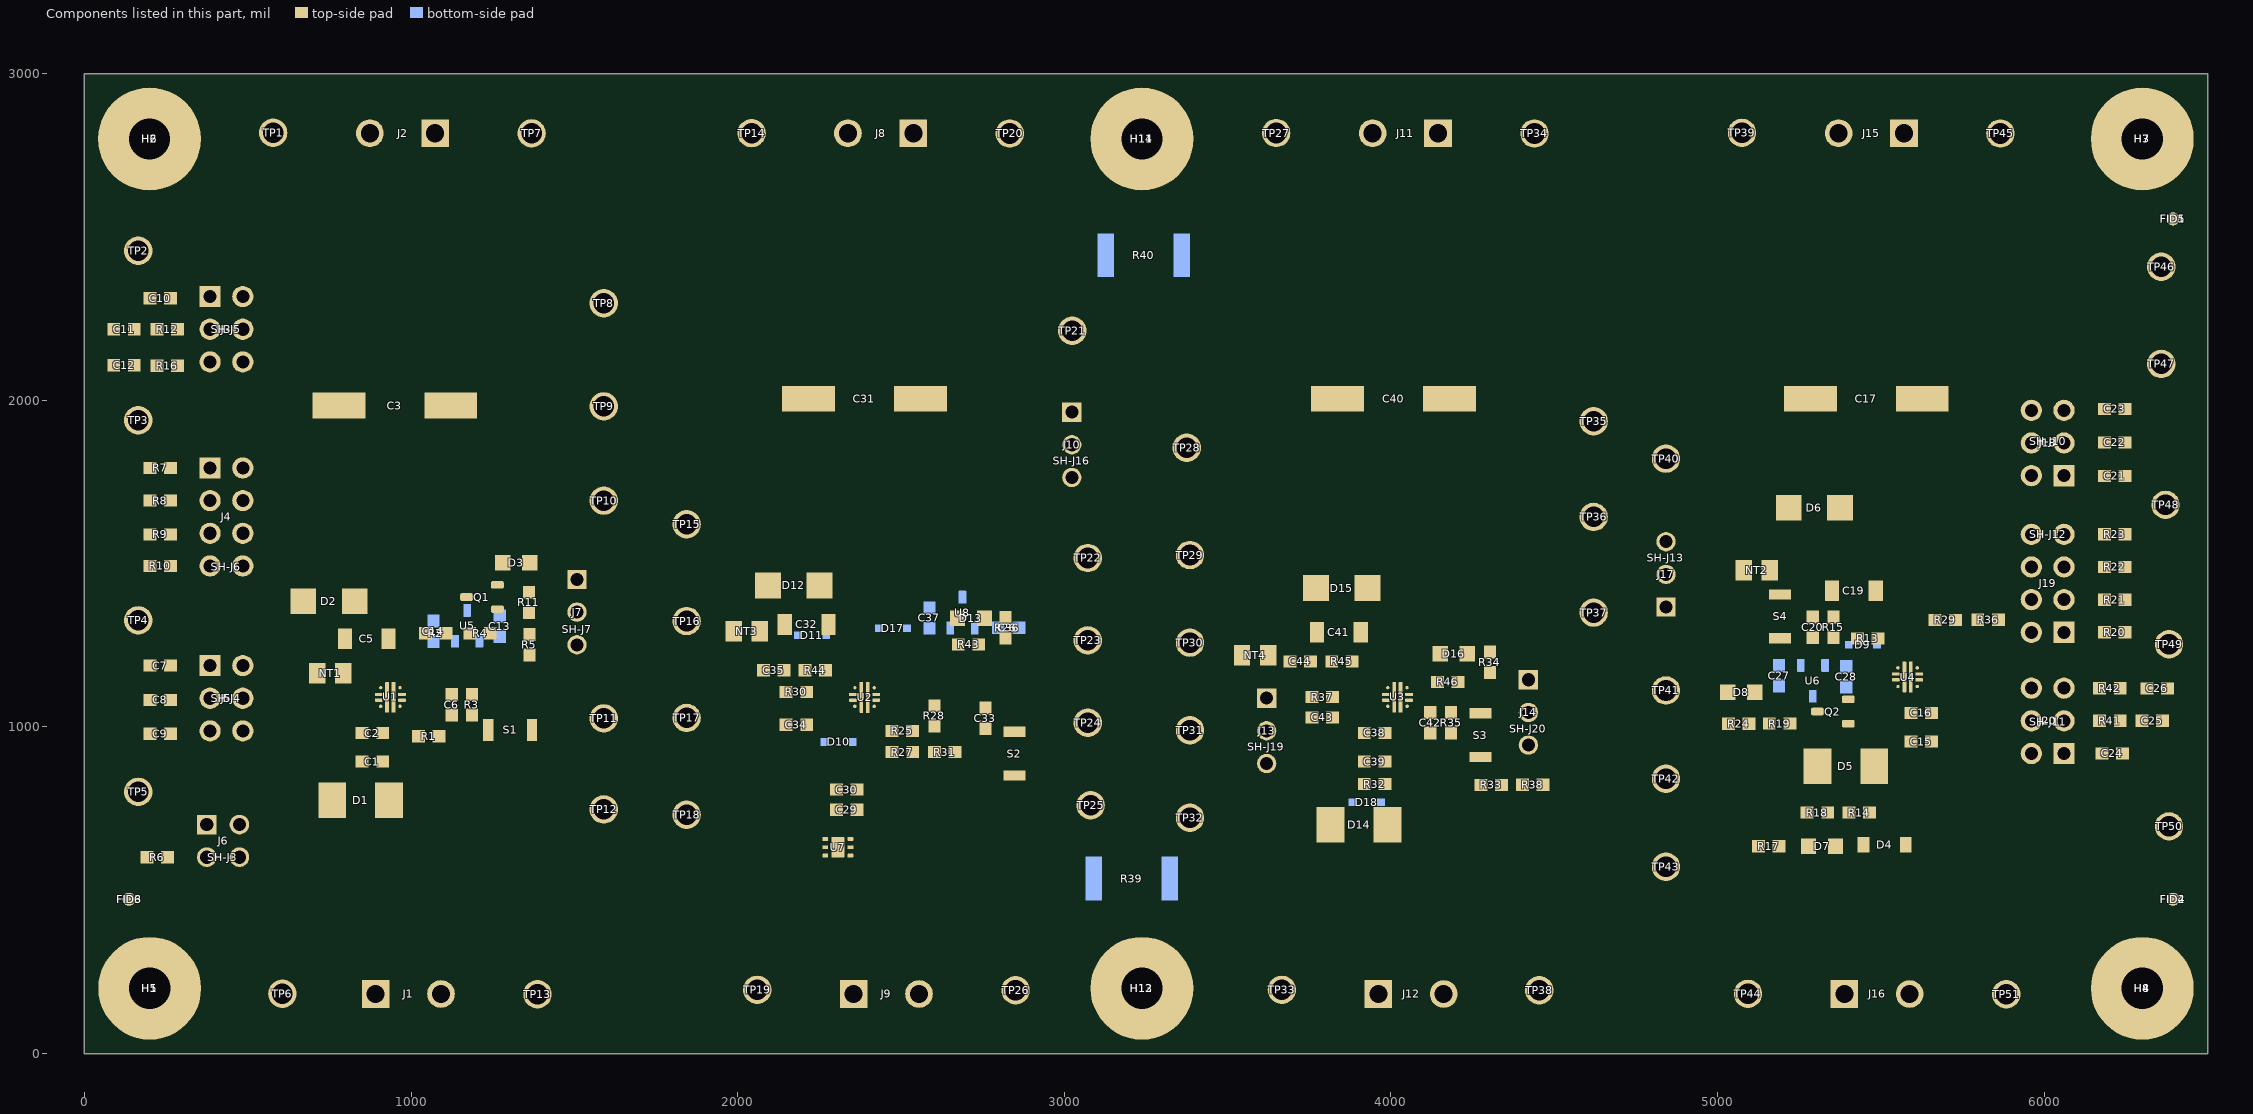
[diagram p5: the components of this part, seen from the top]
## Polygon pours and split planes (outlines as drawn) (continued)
VCC on L1-Top Layer "L1-Top Layer-VCC" (solid, remove dead copper, pour order 124): 4321.73,1186.39 4327.4,1180.72 4327.4,1109.92 4320.01,1102.53 4194.91,1102.53 4183.45,1113.98 4183.45,1175.56 4194.28,1186.39
EN/UVLO3 on L1-Top Layer "L1-TOP_LAYER_EN/UVLO3_P162" (solid, remove dead copper, pour order 162): 4212.28,1024.61 4242.87,994.02 4346.46,994.02 4358.21,1005.77 4358.21,1054.75 4348.36,1064.6 4334.62,1064.6 4139.25,1064.6 4138.63,1063.98 4070.48,1063.98 4065.39,1069.06 4045.32,1069.06 4043.94,1067.69 4043.94,1046.03 4043.35,1045.44 4064.18,1024.61
VIN2 on L1-Top Layer "L1-TOP_LAYER_VIN2_P146" (solid, remove dead copper, pour order 146): 2394.22,1137.83 2394.22,1350.37 2423,1379.15 2515.1,1379.15 2534.16,1360.1 2534.16,1239.58 2447.71,1153.13 2417.43,1153.13 2402.13,1137.83
EN/UVLO2 on L1-Top Layer "L1-TOP_LAYER_EN/UVLO2_P140" (solid, remove dead copper, pour order 140): 2915.72,949.12 2925.03,958.43 2925.03,1011.23 2917.02,1019.23 2809.39,1019.23 2557.96,1019.23 2509.11,1068.08 2422.91,1068.08 2416.88,1062.05 2416.88,1043.34 2428.82,1031.4 2484,1031.4 2513,1002.4 2513,960.76 2524.63,949.12
EN/UVLO1 on L1-Top Layer "L1-TOP_LAYER_EN/UVLO1_P106" (solid, remove dead copper, pour order 106): 984.02,1067.1 970.24,1067.1 966.3,1063.16 966.3,1046.86 988.13,1025.03 1040.59,1025.03 1064.41,1001.2 1064.41,941.2 1068.58,937.03 1266.53,937.03 1282.58,953.08 1282.58,1036.03 1260.15,1058.47 992.64,1058.47
PGND1 on L4-Bottom Layer "L4-BOTTOM_LAYER_PGND1_P126" (solid, remove dead copper, pour order 126): 1580,25.8 1655.7,101.5 1655.7,2912.4 1578.1,2990 82.9,2990 26.8,2933.9 26.8,59.6 60.6,25.8
PGND on L4-Bottom Layer "L4-BOTTOM_LAYER_PGND_P226" (solid, remove dead copper, pour order 226): 4585.87,40.34 4695.4,149.87 4695.4,2885.6 4636,2945 1784.9,2945 1723,2883.1 1724.19,95.21 1779.06,40.34
VIN2 on L4-Bottom Layer "L4-BOTTOM_LAYER_VIN2_P154" (solid, remove dead copper, pour order 154): 3231.29,630.77 3222.86,639.2 2889.76,639.2 2759.52,769.44 2762.72,1034.68 2523.89,1273.51 2523.89,1369.94 2514.68,1379.15 2432.87,1379.15 2402.6,1348.88 2402.6,1045.78 2338.82,982 2338.82,399.9 2462.26,276.47 2462.26,60.02 2490.18,32.1 3090.91,32.1 3135.05,76.24 3135.05,333.15 3231.29,429.39
VOUT2 on L4-Bottom Layer "L4-BOTTOM_LAYER_VOUT2_P196" (solid, remove dead copper, pour order 196): 2960.48,1931.62 2960.48,2014.09 3004.45,2058.06 3139.81,2054.35 3232.6,2147.14 3232.6,2585.55 3212.34,2605.82 3164.54,2605.82 3141.65,2630.38 3141.65,2846.65 3033.76,2954.54 2447.81,2954.54 2439.2,2945.93 2439.2,2102.53 2226.61,1889.94 2226.61,1717.34 2226.61,1279.72 2265.99,1240.35 2295.9,1210.44 2295.9,1050.81 2312.6,1034.11 2361.86,1034.11 2382.7,1054.95 2382.7,1353.85 2425.15,1396.3 2546.45,1396.3 2957.83,1807.68
PGND4 on L4-Bottom Layer "L4-BOTTOM_LAYER_PGND4_P224" (solid, remove dead copper, pour order 224): 4713.4,862.5 4713.4,138.4 4811.2,40.6 6179,40.6 6464.2,325.8 6464.2,2894.4 6377.3,2981.3 4813.97,2981.3 4713.4,2880.73
VIN3 on L4-Bottom Layer "L4-BOTTOM_LAYER_VIN3_P166" (solid, remove dead copper, pour order 166): 4066.97,168.05 4122.26,112.75 4506.17,112.75 4547.4,156.11 4547.4,833.57 4518.32,862.66 4320.9,862.66 4091.58,1091.99 4091.68,1120.37 4074.09,1137.96 4028.95,1137.96 4023.4,1132.42 4023.4,1043.21 3949.81,969.62 3949.81,679.45 3907.03,636.67 3548.93,636.67 3260.84,636.67 3249.05,624.88 3249.05,430.58 3366.52,313.1 4031.44,313.1 4066.97,277.57
VOUT3 on L4-Bottom Layer "L4-BOTTOM_LAYER_VOUT3_P184" (solid, remove dead copper, pour order 184): 4015.9,1168.27 4042.7,1195.07 4290.4,1195.07 4517.26,1421.93 4517.26,1685.96 4517.6,2056.5 4517.6,2859.1 4491.1,2885.6 4048.8,2885.6 4025,2861.8 4025,2740.38 3964.92,2680.3 3346.83,2680.3 3260.84,2594.3 3260.84,2362.67 3284.91,2338.6 3814.08,2338.6 3885.8,2266.87 3885.8,1999.4 3885.8,1073.37 3918.42,1040.76 4001.01,1040.76 4015.9,1055.65
VOUT4 on L4-Bottom Layer "L4-BOTTOM_LAYER_VOUT4_P208" (solid, remove dead copper, pour order 208): 5931.38,2039.88 6453.27,2039.88 6457.48,2044.08 6457.48,2895.65 6393.48,2959.66 5506.46,2959.66 5490.1,2943.3 5490.1,2903.44 5490,2184.78 5311.32,2006.1 5311.32,1588.78 5425.7,1474.4 5425.7,1404.06 5462.67,1367.1 5528.38,1367.1 5585.41,1310.07 5585.41,1193.04 5585.47,1114.8 5594.29,1105.99 5651.69,1105.99 5683.2,1137.5 5683.2,1791.7
NetC28_1 on L4-Bottom Layer "L4-Bottom Layer-NetC28_1" (solid, pour order 212): 5424.95,1178.25 5412.19,1165.49 5314.78,1165.49 5303.34,1176.93 5303.34,1260.62 5309.82,1267.11 5418.51,1267.11 5424.95,1260.67
VIN4 on L4-Bottom Layer "L4-BOTTOM_LAYER_VIN4_P210" (solid, remove dead copper, pour order 210): 5577.11,1296.47 5526.18,1347.4 5481.51,1347.4 5459.4,1325.29 5459.4,998.8 5459.4,317.36 5495.1,281.66 5495.1,132.63 5506.29,121.44 5941.22,121.44 5984.29,164.51 5984.29,546.91 5839.95,691.25 5616.6,914.6 5616.6,1066.5 5577.11,1105.99
GND1 on L2-GND1 "L2-GND1_GND1_P120" (solid, remove dead copper, pour order 120): 1580,25.8 1655.7,101.5 1655.7,2912.4 1578.1,2990 82.9,2990 26.8,2933.9 26.8,59.6 60.6,25.8
GND2 on L2-GND1 "L2-GND1_GND2_P176" (solid, remove dead copper, pour order 176): 1723,96.6 1779,40.6 3167.8,40.6 3216.4,89.2 3216.4,2869.9 3126.64,2959.66 1799.56,2959.66 1723,2883.1 1723,96.4 1744.8,74.6
GND4 on L2-GND1 "L2-GND1_GND4_P180" (solid, remove dead copper, pour order 180): 4713.4,862.5 4713.4,138.4 4811.2,40.6 6179,40.6 6464.2,325.8 6464.2,2894.4 6377.3,2981.3 4863.9,2981.3 4713.4,2830.8
GND3 on L2-GND1 "L2-GND1_GND3_P178" (solid, remove dead copper, pour order 178): 3305.58,40.6 4586.13,40.6 4684.9,139.37 4684.9,2841.9 4581.8,2945 3304.32,2945 3249,2889.68 3249,97.18
PGND1 on L3-PWR/SIG "L3-PWR/SIG_PGND1_P130" (solid, remove dead copper, pour order 130): 1580,25.8 1655.7,101.5 1655.7,2912.4 1578.1,2990 82.9,2990 26.8,2933.9 26.8,59.6 60.6,25.8
PGND on L3-PWR/SIG "L3-PWR/SIG_PGND_P232" (solid, remove dead copper, pour order 232): 1755.4,39.7 4585.23,39.7 4684.9,139.37 4684.9,2841.9 4581.8,2945 1730,2945 1691.45,2906.45 1691.45,103.65
PGND4 on L3-PWR/SIG "L3-PWR/SIG_PGND4_P220" (solid, remove dead copper, pour order 220): 4713.78,862.12 4713.78,138.03 4811.58,40.23 6179.38,40.23 6464.58,325.43 6464.58,2894.02 6377.68,2980.93 4864.28,2980.93 4713.78,2830.43

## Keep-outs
Keep-Out Layer:
  circle w10: c3237.9,2800 r182.44
  circle w10: c3237.9,200.5 r182.44
  circle w10: c200,200 r182.44
  circle w10: c6300,200 r182.44
  circle w10: c6300,2800 r182.44
  circle w10: c200,2800 r182.44
  text ".Layer_Name" at 357.57,-1124.59 h60

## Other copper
L1-Top Layer:
  region net VOUT1: 921.59,1149.87 916.86,1154.6 896.25,1154.6 896.25,1165.49 904.09,1173.33 928.07,1173.33 929.8,1171.6 929.8,1152.46 932.39,1149.87 932.39,1137.87 921.59,1137.9
  region net VIN1: 951.82,1137.84 951.82,1149.84 941.02,1149.84 941.02,1137.86
  region net VIN1: 941,1043.6 941,1031.6 951.8,1031.6 951.8,1043.58
  region net PGND1: 1315.66,1454.75 1231.53,1454.75 1225.62,1448.85 1225.62,1400.38 1237.78,1388.22 1315.32,1388.22 1325.75,1398.65 1325.75,1444.66
  pour cut-out: 5246.55,666.32 5377.86,666.32 5381.67,670.13 5381.67,703.99 5374.34,711.32 5306.68,711.32 5302.8,715.2 5302.8,777.6 5293.63,786.77 5293.63,791.26 5294.4,791.26 5305.43,780.23 5305.42,719.32 5378.03,719.32 5386.53,710.82 5384.48,708.77 5384.48,658.32 5236.38,658.32 5224.78,669.92 5224.78,671.21 5230.99,671.21 5235.8,666.4
  pour cut-out: 2847.32,1377.14 2850.6,1380.42 2544.53,1380.42 2543.26,1379.15 2543.26,1052.46 2548.56,1047.16 2548.56,1158.8 2556.77,1167.01 2829.45,1167.01 2847.32,1184.88
  pour cut-out: 3218.38,1379.15 3223.07,1379.15 3232.6,1369.62 3232.6,1380.42
  pour cut-out: 4678.65,1267.41 4688.66,1267.41 4695.4,1260.67 4695.4,1271.29
  pour cut-out: 4420.6,1002.51 4376.58,1002.51 4369.03,994.96 4357.28,994.96 4352.34,999.9 4358.21,1005.77 4417.34,1005.77
  pour cut-out: 4373.51,1005.77
  pour cut-out: 4358.2,1096.6 4356.02,1096.6 4342.69,1109.92 4342.69,1256.82 4353.29,1267.41 4353.29,1268.07 4346.46,1274.9 4329.09,1274.9 4327.4,1273.21 4327.4,1096.54 4332.54,1091.4 4352.99,1091.4 4358.21,1096.62
  pour cut-out: 1397,1532.4 1395.18,1534.22 1213.34,1534.22 1141.43,1462.31 1141.43,1385.38 1149.41,1377.4 1225.29,1377.4 1236.5,1366.18 1236.5,1344.87 1241.18,1340.2 1270.93,1340.2 1296.71,1314.41 1296.71,1195.25 1291.11,1189.64 1286.89,1189.64 1286.89,1180.61 1310.49,1157.01 1353.73,1157.01 1397,1200.28
  pour cut-out: 1645.72,1557.64 1666.4,1557.64 1671.67,1552.38 1677.26,1552.38 1680.4,1555.52 1680.4,1566.48 1676.08,1570.79 1658.86,1570.79
  pour cut-out: 1645.52,927.16 1666.2,927.16 1671.47,932.42 1677.06,932.42 1680.2,929.28 1680.2,918.32 1675.88,914.01 1658.66,914.01
  pour cut-out: 1297.88,953.08 1297.88,932.4 1303.14,927.13 1303.14,921.54 1300,918.4 1289.05,918.4 1284.73,922.72 1284.73,939.94
  pour cut-out: 2170.16,1349.47 2182.73,1349.47 2191.2,1341 2197.22,1341 2199.18,1342.97 2199.18,1356.05 2195.14,1360.1 2180.79,1360.1
  region net PGND: 2326.39,590.27 2329.85,586.8 2329.85,583.58 2324.42,578.14 2287.98,578.14 2287.01,579.1 2287.01,602.07 2290.22,605.28 2290.22,678.84 2290.67,678.4 2328,678.4 2326.38,676.79
  region net VIN2: 2336.23,662.43 2336.23,598.77 2344.74,590.26 2359.51,590.26 2360.31,591.06 2360.31,666.13 2356.84,669.6 2343.4,669.6
  pour cut-out: 6187.93,354.76 6110.91,354.76 6100.64,365.03 6099.24,363.63 6099.24,352.63 6113.38,338.49 6171.66,338.49
  pour cut-out: 3150.4,2834.95
  pour cut-out: 3237.4,5.25
  pour cut-out: 798.28,845.83 863.53,845.83 871.87,854.17 871.87,848.15 864.46,840.74 803.71,840.74 798.46,846
  pour cut-out: 5444.53,1308.27 5452.87,1308.27 5455.9,1311.3 5455.9,1352.2 5455.92,1352.22 5457.85,1350.28 5457.85,1307.95 5455.9,1306 5446.79,1306
  pour cut-out: 5274.23,1584.05 5294.42,1584.05 5300.51,1577.96 5300.51,1584.3 5296.03,1588.78 5278.97,1588.78
  region net PGND4: 5377.35,1039.4 5370.21,1046.54 5370.21,1103.39 5374.79,1107.59 5428.53,1107.59 5452,1107.76 5460.58,1099.18 5460.58,1057.28 5442.7,1039.4
  pour cut-out: 5373.78,1037.12 5363.64,1047.26 5362.8,1047.26 5362.8,1107 5371.96,1116.16 5422.04,1116.16 5460.94,1115.86 5470.46,1106.34 5470.46,1063.19 5444.39,1037.12
  region net VOUT4: 5592.54,1209.06 5595.27,1209.06 5601.45,1215.24 5614.75,1215.24 5620.84,1221.34 5620.84,1248.68 5613.72,1255.8 5613.72,1254.8 5586.4,1227.47 5586.4,1215.2
  region net VIN4: 5551.06,1226.29 5565.72,1211.63 5565.72,1205.9 5571.15,1200.48 5575.59,1200.48 5577.4,1202.29 5577.4,1247.05 5551.56,1247.05 5549.98,1245.47
  region net VIN4: 5580.19,1100.77 5571.63,1109.32 5571.63,1103.7 5558.63,1090.7 5551.3,1090.7 5551.3,1081.22 5558,1074.51 5579.33,1074.51 5587.83,1083.01 5587.83,1093.13
  region net VOUT3: 4020.2,1145.1 4009.69,1134.59 3989.29,1155.5 4016.59,1155.5 4025.93,1146.16
  region net VIN3: 4032.06,1049.66 4016.81,1034.41 4023.05,1028.18 4044.93,1028.18 4035,1038.11 4035,1050
  region net VIN2: 2417.2,1153.5 2397.99,1134.29 2397.99,1149.27 2411.58,1162.86
  region net VOUT2: 2353.75,1152.59 2360.31,1152.59 2374.8,1138.1 2381.78,1145.07 2381.78,1146.99 2382.45,1147.67 2382.45,1160.8 2378.09,1165.17 2360.25,1165.17
  pour cut-out: 200,3034.45
  text ".Layer_Name" at 357.57,-1124.59 h60
L2-GND1:
  text ".Layer_Name" at 356.57,-1126.59 h60
L3-PWR/SIG:
  text ".Layer_Name" at 357.57,-1126.59 h60
L4-Bottom Layer:
  region net VIN1: 1144.3,1282.03 1026.71,1282.03 957.3,1212.63 957.3,1197.02 997.52,1156.8 1058.44,1156.8 1146.31,1244.67 1146.31,1280.03
  pour cut-out: 3934.52,969.62 3934.52,1003.03 3907.6,1029.94 3923.09,1029.94 3938.99,1014.03 3938.99,974.1
  pour cut-out: 3284.91,2323.31 3258.69,2323.31 3246.73,2311.35 3246.73,2345.75 3247.89,2346.91
  region net VOUT4: 5598.74,1105.99 5585.6,1119.13 5585.6,1208.57 5592.27,1215.24 5598.04,1215.24 5606.39,1206.89 5606.39,1113.65
  region net VIN4: 5570.12,1198.53 5577.5,1191.15 5577.5,1105.6 5591.94,1091.16 5564.21,1091.16 5556.9,1098.48 5556.9,1189.99
  region net VIN3: 4057.83,1045.42 4057.83,1125.15 4045.03,1137.96 4028.95,1137.96 4023.8,1132.82 4023.8,1032.78 4019.73,1028.71 4041.13,1028.71
  region net VOUT3: 3992.11,1040.76 4001.01,1040.76 4015.7,1055.45 4015.7,1157.69 4014.16,1159.23 3999.95,1159.23 3992.11,1151.38
  region net VOUT2: 2384.45,1213.98 2381.6,1216.82 2364.94,1200.16 2364.94,1061.06 2361.13,1057.25 2361.13,1038.72 2366.47,1038.72 2376.87,1049.12 2384.45,1056.7
  region net VIN2: 2405.84,1152.6 2414.88,1152.6 2414.88,1137.02 2412.15,1134.29 2412.15,1031.19 2409.54,1028.58 2398.18,1028.58 2392.65,1034.11 2392.65,1139.4
  text ".Layer_Name" at 357.57,-1124.59 h60

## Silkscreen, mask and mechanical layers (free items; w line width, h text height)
Top Overlay:
  circle w10: c2240.8,657.2 r2.29
  region: 4441.22,2430.42 4141.22,2430.42 4141.22,2330.42 4441.22,2330.42
  lines w6: 2265.4,1134.47 2265.4,1124.2 2268.6,1121 ; 3919.52,1222.4 3929.92,1232.8 3941.6,1232.8 ; 4247.05,866.89 4248.26,866.89 4266.47,885.1 ; 6241.83,982.37 6241.83,982.32 6256.55,967.6 6275.91,967.6 ; 1984.8,842.08 2711.6,842.08 2711.6,1213.6 2393.78,1213.6 1984.8,1213.6 1984.8,842.08
  lines w8: 1184.03,1905.52 1228.53,1905.52 ; 1206.28,1883.27 1206.28,1927.77 ; 2621.14,1913.8 2665.64,1913.8 ; 2643.39,1891.55 2643.39,1936.05 ; 4239.87,1907.89 4284.37,1907.89 ; 4262.12,1885.64 4262.12,1930.14 ; 5697.5,1905.38 5742,1905.38 ; 5719.75,1883.13 5719.75,1927.63
  lines w10: 1703.2,23.1 1703.2,2989 ; 3238,2410.68 3238,408.84 ; 4708.51,2979.9 4708.6,2630.25 ; 4708.6,2166.2 4708.6,23.25
  text "PGND4" at 5007.4,2657.2 h35
  text "PGND" at 3576.11,2656.22 h35
  text "VOUT3" at 4365.4,2655.2 h35
  text "PGND" at 1979.85,2654.4 h35
  text "VOUT2" at 2765.03,2650.12 h35
  text "VOUT1" at 1319.01,2647.84 h35
  text "VOUT4" at 5795.9,2642.73 h35
  text "PGND1" at 517.43,2641.32 h35
  text "VOUT1" at 909.6,2546.8 h35
  text "VOUT2" at 2361,2544.4 h35
  text "VOUT4" at 5392.6,2542.8 h35
  text "VOUT3" at 4188.17,2540.12 h35
  text "For evaluation only; not" at 2993.37,2500.85 h60
  text "FCC approved for resale." at 2993.37,2439.86 h60
  text "DVDT1" at 254.63,2426.72 h35
  text "DVDT1" at 544.6,2280.2 h35
  text "'.PRJ_Title'" at 4459.34,2268.32 h60
  text "PGTH4" at 6292.8,2248.6 h35
  text "PSIL100" at 4588.02,2203.94 h60
  text "E1" at 5002.41,2203.94 h60
  text "GND1" at 1525.69,2116.73 h35
  text "ITIMER4" at 6055.2,2071.2 h35
  text "VCC_EXT2" at 2898.8,2053.8 h35
  text "ILM1" at 248.23,1905.52 h35
  text "VCC" at 3094.1,1837.08 h35
  text "PGTH1" at 1526.9,1809.15 h35
  text "ILM4" at 6351.6,1804.2 h35
  text "FLTB3" at 4524.2,1769.88 h35
  text "GND3" at 3323.8,1692.4 h35
  text "ILM1" at 553.23,1679.72 h35
  text "EN/UVLO4" at 4789.43,1651.92 h35
  text "PG1" at 1271.2,1549 h35
  text "VCC_EXT1" at 1435.4,1525.6 h35
  text "AUX_OFF3" at 4421.15,1483.66 h35
  text "GND2" at 1787.05,1451.2 h35
  text "FLTB2" at 2603.81,1385.98 h35
  text "DVDT3" at 3310.6,1365.8 h35
  text "FLTB2" at 2955.4,1356.2 h35
  text "DVDT4" at 6448.98,1333.65 h35 r90
  text "TIMER1" at 258.18,1285.42 h35
  text "FLTB3" at 4081.67,1280.02 h35
  text "OVLO3" at 4534,1187 h35
  text "dvdt2" at 1749.78,1159.99 h35
  text "PG4" at 5036.76,1154.91 h35
  text "AUX_OFF2" at 2903.1,1105.4 h35
  text "ILM3" at 3331.22,1096.64 h35
  text "TIMER1" at 544.98,1014.98 h35
  text "VCC_EXT4" at 4725.6,950.8 h35
  text "PG1" at 1558.18,863.61 h35
  text "ILM2" at 1788.6,863.61 h35
  text "EN/UVLO2" at 2947,853 h35
  text "EN/UVLO3" at 3260.4,830 h35
  text "OVCSEL1" at 250.8,775.4 h35
  text "PG4" at 4789.03,675.42 h35
  text "OVLO2" at 2959.8,597.8 h35
  text "ENUVLO1" at 1420.7,579.12 h35
  text "OVCSEL1" at 550.2,563.6 h35
  text "ITIMER3" at 3280.6,558.8 h35
  text "TIMER2" at 1775.25,554.4 h35
  text "GND4" at 6328.93,530.46 h35
  text "RPP" at 5285.98,501.06 h35
  text "OVLO4" at 4772.8,398.59 h35
  text "VIN3" at 4026.43,372.52 h35
  text "VIN2" at 2404.11,372.4 h35
  text "VIN1" at 984.22,371.04 h35
  text "VIN4" at 5438.43,370.12 h35
  text "PGND" at 3600.15,26.5 h35
  text "PGND" at 1997.71,24.82 h35
  text "VIN2" at 2783.63,25.13 h35
  text "VIN3" at 4398.23,23.92 h35
  text "PGND4" at 5005.83,17.52 h35
  text "PGND1" at 539.63,17.32 h35
  text "VIN1" at 1329,17.4 h35
  text "VIN4" at 5827.63,14.12 h35
  text ".Layer_Name" at 357.57,-1124.59 h60
Bottom Overlay:
  circle w10: c1207.65,1223.21 r4.7
  circle w10: c2729,1258.1 r4.7
  circle w10: c5253.2,1229.6 r3.06
  text ".Layer_Name" at 357.57,-1124.59 h60
Top Paste:
  text ".Layer_Name" at 357.57,-1124.59 h60
Bottom Paste:
  text ".Layer_Name" at 357.57,-1124.59 h60
Top Solder:
  text ".Layer_Name" at 357.57,-1124.59 h60
  text ".Layer_Name" at 357.57,-1124.59 h60
Bottom Solder:
  text ".Layer_Name" at 357.57,-1124.59 h60
Drill Guide:
  text ".Layer_Name" at 357.57,-1124.59 h60
M1 Board Outline:
  the board outline again, w10
  text ".Layer_Name" at 357.57,-1124.59 h60
M2 Board Dimensions:
  rectangle: -94.43,-666.09 280.57,-541.09
  rectangle: -219.43,-541.09 -94.43,-416.09
  lines w7: -219.43,-541.09 780.57,-541.09 ; -94.43,-666.09 -94.43,-416.09 ; 30.57,-666.09 30.57,-416.09 ; 280.57,-666.09 280.57,-416.09 ; 530.57,-666.09 530.57,-416.09 ; -219.43,-666.09 -219.43,-416.09 780.57,-416.09 780.57,-666.09 -219.43,-666.09
  text ".Layer_Name" at 357.57,-1124.59 h60
M3 3D STEP Top:
  text ".Layer_Name" at 357.57,-1124.59 h60
M4 3D STEP Bottom:
  text ".Layer_Name" at 357.57,-1124.59 h60
M5 Assembly Top:
  circle w10: c5516.52,1177.85 r3.67
  circle w10: c5420.03,1014.47 r3.67
  circle w10: c4073.4,1064.2 r3.67
  circle w10: c2458.34,1067.83 r3.67
  circle w10: c1280.4,1358.2 r3.67
  circle w10: c1000.98,1064.66 r3.67
  lines w6: 1171.64,2265.02 1209.64,2265.02 ; 1190.64,2246.02 1190.64,2284.01 ; 2605,2260 2643,2260 ; 2624,2241 2624,2279 ; 4228.4,2260.8 4266.4,2260.8 ; 4247.4,2241.8 4247.4,2279.8 ; 5672.4,2257.2 5710.4,2257.2 ; 5691.4,2238.2 5691.4,2276.2
  lines w10: -511.43,-1196.26 6088.57,-1196.26 ; -511.43,-992.93 6090.57,-992.93 ; -511.43,-789.59 -511.43,-1399.59 3493.57,-1399.59 6090.57,-1399.59 6090.57,-789.59 -510.93,-789.59 -510.93,-1399.59 1064.57,-1399.59 ; 1953.57,-1399.59 1953.57,-789.59 ; 3220.57,-992.93 3220.57,-789.59 ; 4060.57,-992.93 4060.57,-789.59 ; 4682.57,-1406.09 4682.57,-1203.26
  text "COMPONENTS MARKED 'DNP' SHOULD NOT BE POPULATED." at 934.07,-584.59 h60
  text "ASSEMBLY VARIANT:" at 933.57,-700.09 h60
  text ".VariantName" at 1969.57,-700.09 h60
  text "PCB VIEWED FROM TOP SIDE" at -447.93,-921.76 h60
  text "BOARD #:" at 2028.57,-921.76 h40
  text "REV:" at 3418.57,-921.76 h60
  text ".PCB_Rev" at 3710.07,-921.76 h60
  text "SVN REV:" at 4256.57,-921.76 h60
  text ".VersionControl_RevNumber" at 4762.57,-921.76 h60
  text ".PRJ_Title" at 2327.5,-924.6 h60
  text ".Layer_Name" at 382.1,-1102.8 h60
  text "TID #:" at 2028.57,-1125.09 h60
  text ".TID" at 2574.07,-1125.09 h60
  text ".plot_File_Name" at 201.5,-1326.7 h50
  text "PLOT NAME =" at -447.93,-1330.43 h60
  text "GENERATED    :" at 2030.57,-1330.43 h60
  text ".Print_Date" at 2900.07,-1330.43 h60
  text ".Print_Time" at 3629.07,-1330.43 h60
  text "TEXAS INSTRUMENTS" at 4893.57,-1330.43 h60
M6 Assembly Bottom:
  circle w10: c1208.65,1242.66 r2.24
  circle w10: c2724.86,1283.07 r2.24
  circle w10: c5253.8,1210.2 r2.24
  lines w10: -511.93,-993.43 6090.07,-993.43 ; -509.93,-1196.76 6090.07,-1196.76 ; 896.07,-1406.59 896.07,-1203.76 ; 1518.07,-993.43 1518.07,-790.09 ; 2358.07,-993.43 2358.07,-790.09 ; 3625.07,-1400.09 3625.07,-790.09 ; 4514.07,-1400.09 6089.57,-1400.09 6089.57,-790.09 -511.93,-790.09 -511.93,-1400.09 2085.07,-1400.09 6090.07,-1400.09 6090.07,-790.09
  text "COMPONENTS MARKED 'DNP' SHOULD NOT BE POPULATED." at 5882.57,-584.09 h60
  text ".VariantName" at 4838.57,-700.09 h60
  text "ASSEMBLY VARIANT:" at 5877.57,-700.09 h60
  text ".PRJ_Title" at 3146.6,-908.8 h60
  text ".VersionControl_RevNumber" at 816.07,-922.26 h60
  text "SVN REV:" at 1322.07,-922.26 h60
  text ".PCB_Rev" at 1868.57,-922.26 h60
  text "REV:" at 2160.07,-922.26 h60
  text "BOARD #:" at 3550.07,-922.26 h40
  text "PCB VIEWED FROM BOTTOM SIDE" at 6026.57,-922.26 h60
  text ".TID" at 3004.57,-1125.59 h60
  text "TID #:" at 3550.07,-1125.59 h60
  text ".Layer_Name" at 5419,-1128 h60
  text ".plot_File_Name" at 5376.1,-1330 h50
  text "TEXAS INSTRUMENTS" at 685.07,-1330.93 h60
  text ".Print_Time" at 1949.57,-1330.93 h60
  text ".Print_Date" at 2678.57,-1330.93 h60
  text "GENERATED    :" at 3548.07,-1330.93 h60
  text "PLOT NAME =" at 6026.57,-1330.93 h60
M7 LPKF Text Top:
  text ".Layer_Name" at 436.7,-1109.9 h60
M8 LPKF Text Bottom:
  text ".Layer_Name" at 399.1,-1097.4 h60
M9 Title Sheet:
  drawing of 57 lines, arcs and shapes, not listed
  text "1" at 520.41,7770.41 h70
  text "2" at 3016.07,7770.41 h70
  text "3" at 5505.42,7770.41 h70
  text "4" at 8012.09,7770.41 h70
  text "5" at 10511.07,7770.41 h70
  text "6" at 13016.07,7770.41 h70
  text "A" at -635.93,6627.41 h70
  text "A" at 14164.07,6627.41 h70
  text "B" at -635.93,4247.41 h70
  text "B" at 14164.07,4247.41 h70
  text "C" at -635.93,1872.41 h70
  text "C" at 14164.07,1872.41 h70
  text "PROJECT TITLE:" at 11124.07,11.41 h45
  text ".PRJ_Title" at 11174.07,-121.92 h70
  text "DESIGNED FOR:" at 11124.07,-289.59 h45
  text ".PRJ_Customer" at 11174.07,-429.59 h70
  text "D" at -635.93,-497.59 h70
  text "D" at 14164.07,-497.59 h70
  text "FILE NAME:" at 11124.07,-589.59 h45
  text ".PCB_File_Name_No_Path" at 11174.07,-709.59 h70
  text "Texas Instruments (TI) and/or its licensors do not warrant the accuracy or completeness of this specification" at 6154.57,-871.43 h45
  text "ENGINEER:" at 11124.07,-879.59 h45
  text "LAYOUT BY:" at 12629.07,-879.59 h45
  text "or any information contained therein. TI and/or its licensors do not warrant that this design will meet" at 6109.59,-984.1 h45
  text ".PRJ_Engineer" at 11174.07,-1034.59 h70
  text ".PCB_Layout" at 12679.57,-1034.59 h70
  text "the specifications, will be suitable for your application or fit for any particular purpose, or will operate in" at 6109.59,-1096.76 h45
  text ".Layer_Name" at 357.57,-1124.59 h60
  text "ALTIUM DESIGNER VERSION:" at 12629.07,-1189.59 h45
  text "an implementation. TI and/or its licensors do not warrant that the design is production worthy. You should" at 6109.59,-1209.43 h45
  text "completely validate and test your design implementation to confirm the system functionality for your application." at 6154.57,-1322.09 h45
  text ".print_Scale" at 11174.07,-1322.92 h70
  text ".Application_BuildNumber" at 12679.57,-1322.92 h70
  text "1" at 520.41,-1529.59 h70
  text "2" at 3016.07,-1529.59 h70
  text "3" at 5505.42,-1529.59 h70
  text "4" at 8012.09,-1529.59 h70
  text "5" at 10511.07,-1529.59 h70
  text "6" at 13016.07,-1529.59 h70
M10 Fab Notes:
  drawing of 189 lines, arcs and shapes, not listed
  text "NOTE:" at 5425.9,6937.2 h60
  text "1.ALL VIAS ARE NON TENTED." at 5667.89,6830.6 h60
  text "2.THIS IS NOT AN IMPEDANCE CONTROLLED BOARD." at 5667.89,6704.6 h60
  text "3. VENDOR MAY ADJUST SOLDERMASK WHEREVER SOLDERMASK PADS ARE THE SAME SIZE (1:1) AS PER THE MANUFACTURING CAPABILITIES" at 5667.89,6575.11 h60
  text "AND ALL OTHER SOLDER MASK PADS SHALL NOT BE MODIFIED, PROVIDED NO ADJACENT COPPER IS EXPOSED AND NO CONFLICT IS PRODUCED" at 5774.62,6476.12 h60
  text "WITH ANY STATED \"VIA TENTING/COVERING\" REQUIREMENTS." at 5774.62,6382.83 h60
  text "DESIGN INFORMATION" at 12162.59,6090.08 h60
  text "MIN. TRACK WIDTH:" at 11518.03,5957.95 h60
  text "9" at 12614.28,5957.96 h60
  text "MIL" at 12769.03,5957.95 h60
  text "MIN. CLEARANCE:" at 11518.03,5833.83 h60
  text "5.118" at 12563.8,5834.2 h60
  text "MIL" at 12845.1,5834.1 h60
  text "MIN. VIA PAD SIZE:" at 11518.03,5709.7 h60
  text "MIL" at 12769.03,5709.7 h60
  text "14" at 12586.3,5706 h60
  text "0.05mm (2MIL)" at 12213.03,5579.8 h60
  text "MINIMUM ANNULAR RING" at 11188.8,5571.58 h60
  text "EXTERNAL" at 12921.03,5571.58 h60
  text "PER" at 11388.8,5461.45 h60
  text "IPC-D-275 CLASS 2 LEVEL C" at 11608.8,5461.45 h60
  text "MIL, HOLES" at 13097.03,5360.97 h60
  text "+/-" at 12704.57,5352.39 h60
  text "+/-" at 13558.57,5352.39 h60
  text "REGISTRATION TOLERANCES:" at 11188.8,5351.32 h60
  text "METAL" at 12388.57,5351.32 h60
  text "5" at 12964.78,5351.33 h60
  text "3" at 13797.78,5351.33 h60
  text "MIL" at 13914.03,5351.32 h60
  text "HOLE SIZE TOLERANCE (UNLESS OTHERWISE SPECIFIED):" at 11188.8,5253.01 h60
  text "+/-" at 13558.57,5250.14 h60
  text "3" at 13797.78,5249.08 h60
  text "MIL" at 13914.03,5249.07 h60
  text "MATERIAL:" at 11114.03,5111.43 h60
  text "FR-4 High Tg" at 12100.48,4982.9 h60
  text "X" at 11956.04,4974.91 h60
  text "FR-408" at 11535.04,4970.39 h60
  text "OTHER" at 13023.03,4970.39 h60
  text "X" at 11735.04,4824.91 h60
  text "62MIL (1.6mm) +/-10%" at 11837,4822 h60
  text "THICKNESS:" at 11188.8,4819.14 h60
  text "OTHER" at 13140.03,4819.14 h60
  text "TOLERANCE:" at 11188.8,4680.83 h60
  text "X" at 12037.04,4680.83 h60
  text "ANSI IPC-6012 TYPE 3 CLASS 2" at 12215.05,4680.83 h60
  text "OTHER +/-" at 12215.03,4536.64 h60
  text "BOW & TWIST:" at 11188.8,4391.45 h60
  text "X" at 12037.04,4391.45 h60
  text "ANSI IPC-6012 TYPE 3 CLASS 2" at 12215.05,4391.45 h60
  text "OTHER +/-" at 12215.03,4244.75 h60
  text "DRILLING:" at 11114.03,4114.14 h60
  text "NC_DRILL FILES" at 12875.03,4008.95 h60
  text "REFERENCE:" at 11188.8,4005.01 h60
  text "X" at 11846.04,4004.91 h60
  text "AS SHOWN" at 12024.03,4005.01 h60
  text "X" at 12747.04,4005.01 h60
  text "OTHER" at 13173.03,3862.76 h60
  text "PTH COPPER THICKNESS:" at 11188.48,3859.23 h60
  text "X" at 12327.72,3859.23 h60
  text "20-30 um" at 12455.71,3859.23 h60
  text "BOARD FINISH:" at 11114.03,3711.63 h60
  text "SILKSCREEN:" at 11269.26,3601.51 h60
  text "X" at 12227.04,3601.51 h60
  text "TOP" at 12344.03,3601.51 h60
  text "BOTTOM" at 12855.03,3601.51 h60
  text "X" at 12734.64,3595.9 h60
  text "SILKSCREEN COLOR:" at 11269.26,3446.32 h60
  text "X" at 12226.04,3446.32 h60
  text "WHITE" at 12344.03,3446.32 h60
  text "OTHER" at 12855.03,3446.32 h60
  text "X" at 12357.04,3302.87 h60
  text "GREEN" at 12475.03,3302.87 h60
  text "OTHER" at 13093.03,3302.87 h60
  text "SOLDER RESIST COLOR:" at 11269.26,3296 h60
  text "X" at 12357.04,3148.62 h60
  text "MATTE" at 12475.03,3148.62 h60
  text "SEMI-GLOSS" at 13092.57,3147.98 h60
  text "IMMERSION GOLD (ENIG)" at 12175.03,2975.84 h60
  text "ENEPIG" at 13512.57,2968.62 h60
  text "SURFACE FINISH:" at 11114.03,2967.62 h60
  text "X" at 11997.04,2967.62 h60
  text "IMM. TIN/SILVER OR EQUIV" at 11443.57,2830.31 h60
  text "OTHER" at 12875.03,2826.37 h60
  text "ARRAY/PANEL:" at 11114.03,2670.99 h60
  text "X" at 11993,2665 h60
  text "CUT AND TRIM PER M1 BOARD OUTLINE" at 12175.03,2662.77 h60
  text "N.C. ROUTE" at 12175.03,2526.8 h60
  text "V. SCORE" at 13041.03,2526.8 h60
  text "CERTIFICATION:" at 11114.03,2397.68 h60
  text "MATERIALS AND WORKMANSHIP FOR ALL PCBS" at 11839.03,2397.68 h60
  text "TO MEET OR EXCEED THE REQUIREMENTS OF:" at 11839.03,2303.61 h60
  text "X" at 11476.54,2174.99 h60
  text "ANSI IPC-A-600F CLASS ->" at 11604.54,2174.99 h60
  text "X" at 13252.54,2174.99 h60
  text "2" at 13362.54,2174.99 h60
  text "1" at 13047.54,2173.49 h60
  text "3" at 13716.54,2173.49 h60
  text "X" at 12288.54,2027.3 h60
  text "RoHS" at 12416.54,2027.3 h60
  text "OTHER" at 13060.94,2027.3 h60
  text "PER ORDER" at 13458,2027.3 h60
  text "ALL BOARDS MUST MEET OR EXCEED UL94-V0 REQUIREMENTS." at 11141.57,1873.47 h60
  text "PCB MUST BEAR THE UL94V-0 UL REGISTERED MATERIAL ID NUMBER" at 11141.57,1757.41 h60
  text "ADDITIONAL REQUIREMENTS:" at 11114.03,1587.99 h60
  text "MICROSECTION:" at 11188.8,1480.86 h60
  text "YES" at 12094.54,1480.86 h60
  text "REQUIRED" at 12956.03,1336.53 h60
  text "BARE BOARD ELEC. TEST:" at 11188.8,1333.67 h60
  text "NONE" at 12494.54,1333.67 h60
  text "X" at 12838.04,1333.67 h60
  text "PER ORDER" at 13548.03,1333.67 h60
  text "XX MIL VIAS REQUIRE NON-CONDUCTIVE FILL AND PLANARIZE" at 11356.95,1128.72 h59
  text "ALL 7.87 AND 12 MIL VIAS REQUIRE TENTING ON BOTH SIDES" at 11364.95,1024.75 h60
  text "OUTER XX MIL TRACES REQUIRE 50 OHM SINGLE-ENDED IMPEDANCE" at 11363.97,861.36 h57
  text "LAYER 2 & 3 (INNER LAYERS) XX MIL WIDE, XX MIL SPACE / TRACES REQUIRE 100 OHM DIFFERENTIAL IMPEDANCE" at 11355.97,625.65 h60
  text ".Layer_Name" at 357.57,-1124.59 h60
M11 Gerber Information:
  lines w10: -511.43,-1196.26 6088.57,-1196.26 ; -511.43,-992.93 6090.57,-992.93 ; -511.43,-789.59 -511.43,-1399.59 3493.57,-1399.59 6090.57,-1399.59 6090.57,-789.59 -510.93,-789.59 -510.93,-1399.59 1064.57,-1399.59 ; 1953.57,-1399.59 1953.57,-789.59 ; 3220.57,-992.93 3220.57,-789.59 ; 4060.57,-992.93 4060.57,-789.59 ; 4682.57,-1406.09 4682.57,-1203.26
  text "ALL ARTWORK VIEWED FROM TOP SIDE" at -447.93,-921.76 h60
  text "BOARD #:" at 2028.57,-921.76 h40
  text "REV:" at 3418.57,-921.76 h60
  text ".PCB_Rev" at 3710.07,-921.76 h60
  text "SVN REV:" at 4256.57,-921.76 h60
  text ".VersionControl_RevNumber" at 4762.57,-921.76 h60
  text ".PRJ_Title" at 2331.9,-924 h60
  text ".Layer_Name" at 291.4,-1112.8 h60
  text "LAYER NAME =" at -447.93,-1124.59 h60
  text "TID #:" at 2028.57,-1125.09 h60
  text ".TID" at 2574.07,-1125.09 h60
  text "PLOT NAME =" at -447.93,-1330.43 h60
  text "GENERATED    :" at 2030.57,-1330.43 h60
  text ".Print_Date" at 2900.07,-1330.43 h60
  text ".Print_Time" at 3629.07,-1330.43 h60
  text "TEXAS INSTRUMENTS" at 4893.57,-1330.43 h60
  text ".plot_File_Name" at 203.9,-1330.7 h50
M12 Stackup:
  drawing of 269 lines, arcs and shapes, not listed
  text "Layer" at 5753.16,5960.8 h60
  text "Name" at 6163.07,5960.8 h60
  text "Material" at 7152.8,5960.8 h60
  text "Thickness" at 8012.56,5960.8 h60
  text "Constant" at 8662.4,5960.8 h60
  text "Board Layer Stack" at 9232.26,5960.8 h60
  text "Top Overlay" at 6163.07,5840.8 h60
  text "Top Solder" at 6163.07,5720.8 h60
  text "Solder Resist" at 7152.8,5720.8 h60
  text "0.40mil" at 8012.56,5720.8 h60
  text "3.5" at 8662.4,5720.8 h60
  text "1" at 5753.16,5600.8 h60
  text "L1-Top Layer" at 6163.07,5600.8 h60
  text "Copper" at 7152.8,5600.8 h60
  text "2.80mil" at 8012.56,5600.8 h60
  text "Dielectric 3" at 6163.07,5480.8 h60
  text "FR-4 HIGH TG" at 7152.8,5480.8 h60
  text "10.00mil" at 8012.56,5480.8 h60
  text "4.2" at 8662.4,5480.8 h60
  text "2" at 5753.16,5360.8 h60
  text "L2-GND1" at 6163.07,5360.8 h60
  text "Copper" at 7152.8,5360.8 h60
  text "1.40mil" at 8012.56,5360.8 h60
  text "Dielectric 2" at 6163.07,5240.8 h60
  text "FR-4 HIGH TG" at 7152.8,5240.8 h60
  text "35.00mil" at 8012.56,5240.8 h60
  text "4.2" at 8662.4,5240.8 h60
  text "3" at 5753.16,5120.8 h60
  text "L3-PWR/SIG" at 6163.07,5120.8 h60
  text "Copper" at 7152.8,5120.8 h60
  text "1.40mil" at 8012.56,5120.8 h60
  text "Dielectric1" at 6163.07,5000.8 h60
  text "FR-4 HIGH TG" at 7152.8,5000.8 h60
  text "10.00mil" at 8012.56,5000.8 h60
  text "4.2" at 8662.4,5000.8 h60
  text "4" at 5753.16,4880.8 h60
  text "L4-Bottom Layer" at 6163.07,4880.8 h60
  text "Copper" at 7152.8,4880.8 h60
  text "2.80mil" at 8012.56,4880.8 h60
  text "Bottom Solder" at 6163.07,4760.8 h60
  text "Solder Resist" at 7152.8,4760.8 h60
  text "0.40mil" at 8012.56,4760.8 h60
  text "3.5" at 8662.4,4760.8 h60
  text ".Layer_Name" at 357.57,-1124.59 h60
M13 Component Bodies Top:
  text ".Layer_Name" at 357.57,-1124.59 h60
M14 Component Bodies Bottom:
  text ".Layer_Name" at 357.57,-1124.59 h60
M15 Courtyards Top:
  text ".Layer_Name" at 357.57,-1124.59 h60
M16 Courtyards Bottom:
  text ".Layer_Name" at 357.57,-1124.59 h60
Drill Drawing:
  circle w10: c5723.62,3981.23 r33.33
  lines w10: 7643.7,2924 8231.7,2924 ; 5690.29,3347.9 5756.96,3347.9 5756.96,3414.57 5690.29,3414.57 5690.29,3347.9 ; 5690.29,3497.9 5723.62,3514.57 5756.96,3497.9 5740.29,3531.23 5756.96,3564.57 5723.62,3547.9 5690.29,3564.57 5706.96,3531.23 5690.29,3497.9 ; 5690.29,3647.9 5690.29,3664.57 5706.96,3681.23 5690.29,3697.9 5690.29,3714.57 5706.96,3714.57 5723.62,3697.9 5740.29,3714.57 5756.96,3714.57 5756.96,3697.9 5740.29,3681.23 5756.96,3664.57 5756.96,3647.9 5740.29,3647.9 5723.62,3664.57 5706.96,3647.9 5690.29,3647.9 ; 5690.29,3814.57 5706.96,3814.57 5723.62,3797.9 5740.29,3814.57 5756.96,3814.57 5740.29,3831.23 5756.96,3847.9 5740.29,3847.9 5723.62,3864.57 5706.96,3847.9 5690.29,3847.9 5706.96,3831.23 5690.29,3814.57 ; 5690.29,4164.57 5756.96,4164.57 5723.62,4097.9 5690.29,4164.57 ; 5690.29,4264.57 5706.96,4264.57 5706.96,4247.9 5740.29,4247.9 5740.29,4264.57 5756.96,4264.57 5756.96,4297.9 5740.29,4297.9 5740.29,4314.57 5706.96,4314.57 5706.96,4297.9 5690.29,4297.9 5690.29,4264.57
  lines w15: 5630.5,3302.9 10921.04,3302.9 ; 5630.5,4352.9 10921.04,4352.9 ; 6181.38,3152.9 6181.38,4502.9 ; 6781.22,3152.9 6781.22,4502.9 ; 7930.88,3152.9 7930.88,4502.9 ; 8436.76,3152.9 8436.76,4502.9 ; 10286.19,3152.9 10286.19,4502.9 ; 5630.5,3152.9 10921.04,3152.9 10921.04,4502.9 5630.5,4502.9 5630.5,3152.9
  text "Symbol" at 5720.5,4397.9 h72
  text "Count" at 6226.38,4397.9 h72
  text "Hole Size" at 6826.22,4397.9 h72
  text "Plated" at 7975.88,4397.9 h72
  text "Drill Layer Pair" at 8481.76,4397.9 h72
  text "Via/Pad" at 10331.19,4397.9 h72
  text "2" at 6226.38,4247.9 h60
  text "7.87mil (0.200mm)" at 6826.22,4247.9 h60
  text "PTH" at 7975.88,4247.9 h60
  text "L1-Top Layer - L4-Bottom Layer" at 8481.76,4247.9 h60
  text "Via" at 10331.19,4247.9 h60
  text "6" at 6226.38,4097.9 h60
  text "125.98mil (3.200mm)" at 6826.22,4097.9 h60
  text "PTH" at 7975.88,4097.9 h60
  text "L1-Top Layer - L4-Bottom Layer" at 8481.76,4097.9 h60
  text "Pad" at 10331.19,4097.9 h60
  text "16" at 6226.38,3947.9 h60
  text "55.12mil (1.400mm)" at 6826.22,3947.9 h60
  text "PTH" at 7975.88,3947.9 h60
  text "L1-Top Layer - L4-Bottom Layer" at 8481.76,3947.9 h60
  text "Pad" at 10331.19,3947.9 h60
  text "24" at 6226.38,3797.9 h60
  text "6.00mil (0.152mm)" at 6826.22,3797.9 h60
  text "PTH" at 7975.88,3797.9 h60
  text "L1-Top Layer - L4-Bottom Layer" at 8481.76,3797.9 h60
  text "Via" at 10331.19,3797.9 h60
  text "51" at 6226.38,3647.9 h60
  text "63.00mil (1.600mm)" at 6826.22,3647.9 h60
  text "PTH" at 7975.88,3647.9 h60
  text "L1-Top Layer - L4-Bottom Layer" at 8481.76,3647.9 h60
  text "Pad" at 10331.19,3647.9 h60
  text "59" at 6226.38,3497.9 h60
  text "40.00mil (1.016mm)" at 6826.22,3497.9 h60
  text "PTH" at 7975.88,3497.9 h60
  text "L1-Top Layer - L4-Bottom Layer" at 8481.76,3497.9 h60
  text "Pad" at 10331.19,3497.9 h60
  text "551" at 6226.38,3347.9 h60
  text "12.00mil (0.305mm)" at 6826.22,3347.9 h60
  text "PTH" at 7975.88,3347.9 h60
  text "L1-Top Layer - L4-Bottom Layer" at 8481.76,3347.9 h60
  text "Via" at 10331.19,3347.9 h60
  text "709 Total" at 6226.38,3197.9 h60
  text "DRILL TOLERANCE" at 7648.7,2942 h40
  text "FOR 6 MIL DRILL +0/- 6 MIL" at 7753.7,2759 h40
  text "FOR 7.87MIL DRILL +0/- 7.87 MIL" at 7753.7,2679.6 h40
  text "FOR 8MIL DRILL +0/- 8 MIL" at 7753.7,2605.4 h40
  text "FOR 12MIL DRILL +0/- 12 MIL" at 7753.7,2531.2 h40
  text "FOR PTH +/-3MILS" at 7753.7,2457 h40
  text ".Layer_Name" at 357.57,-1124.59 h60
M17 Embedded Cavity:
  text ".Layer_Name" at 357.57,-1124.59 h60
M18 Embedded Assembly:
  text ".Layer_Name" at 357.57,-1124.59 h60
M19 Embedded Keepout:
  text ".Layer_Name" at 357.57,-1124.59 h60

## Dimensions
-219.43,-666.09 to 780.57,-666.09 on M2 Board Dimensions
0,0 to 6500,0 on M2 Board Dimensions
0,0 to 0,3000 on M2 Board Dimensions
